# Created by MC2 : Version 2006.09.01.d on 2025/07/22, 15:52:49

###############################################################################
#        Software       : TSMC MEMORY COMPILER 2006.09.01.d
#        Technology     : 65 nm CMOS LOGIC Low Power LowK Cu 1P9M 1.2V
#                         Mixed-vt logic, High-vt SRAM
#        Memory Type    : TSMC 65nm Low Power Dual Port SRAM
#        Library Name   : tsdn65lplla1024x32m4s
#        Library Version: 200a
#        Generated Time : 2025/07/22, 15:52:48
###############################################################################
#
#STATEMENT OF USE
#
#This information contains confidential and proprietary information of TSMC.
#No part of this information may be reproduced, transmitted, transcribed,
#stored in a retrieval system, or translated into any human or computer
#language, in any form or by any means, electronic, mechanical, magnetic,
#optical, chemical, manual, or otherwise, without the prior written permission
#of TSMC. This information was prepared for informational purpose and is for
#use by TSMC's customers only. TSMC reserves the right to make changes in the
#information at any time and without notice.
#
###############################################################################
 
VERSION 5.5 ;
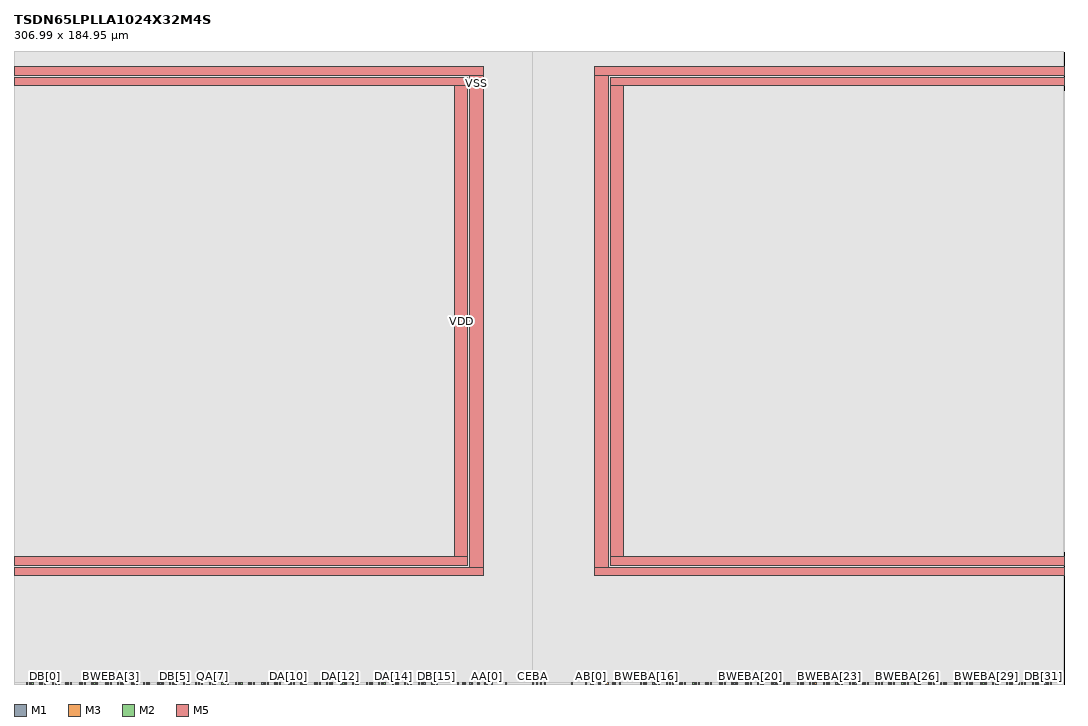
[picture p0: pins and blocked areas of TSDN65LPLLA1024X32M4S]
MACRO TSDN65LPLLA1024X32M4S
	CLASS BLOCK ;
	FOREIGN TSDN65LPLLA1024X32M4S 0.0 0.0 ;
	ORIGIN 0.0 0.0 ;
	SIZE 306.990 BY 184.950 ;
	SYMMETRY X Y R90 ;

	PIN AA[0]
		DIRECTION INPUT ;
		USE SIGNAL ;
		PORT
			LAYER M1 ;
			RECT 137.995 0.000 138.315 0.440 ;
			LAYER M3 ;
			RECT 137.995 0.000 138.315 0.440 ;
			LAYER M2 ;
			RECT 137.995 0.000 138.315 0.440 ;
		END
	END AA[0]

	PIN AA[1]
		DIRECTION INPUT ;
		USE SIGNAL ;
		PORT
			LAYER M1 ;
			RECT 139.555 0.000 139.875 0.440 ;
			LAYER M3 ;
			RECT 139.555 0.000 139.875 0.440 ;
			LAYER M2 ;
			RECT 139.555 0.000 139.875 0.440 ;
		END
	END AA[1]

	PIN AA[2]
		DIRECTION INPUT ;
		USE SIGNAL ;
		PORT
			LAYER M2 ;
			RECT 129.675 0.000 129.995 0.440 ;
			LAYER M3 ;
			RECT 129.675 0.000 129.995 0.440 ;
			LAYER M1 ;
			RECT 129.675 0.000 129.995 0.440 ;
		END
	END AA[2]

	PIN AA[3]
		DIRECTION INPUT ;
		USE SIGNAL ;
		PORT
			LAYER M3 ;
			RECT 131.235 0.000 131.555 0.440 ;
			LAYER M2 ;
			RECT 131.235 0.000 131.555 0.440 ;
			LAYER M1 ;
			RECT 131.235 0.000 131.555 0.440 ;
		END
	END AA[3]

	PIN AA[4]
		DIRECTION INPUT ;
		USE SIGNAL ;
		PORT
			LAYER M3 ;
			RECT 131.755 0.000 132.075 0.440 ;
			LAYER M2 ;
			RECT 131.755 0.000 132.075 0.440 ;
			LAYER M1 ;
			RECT 131.755 0.000 132.075 0.440 ;
		END
	END AA[4]

	PIN AA[5]
		DIRECTION INPUT ;
		USE SIGNAL ;
		PORT
			LAYER M3 ;
			RECT 135.915 0.000 136.235 0.440 ;
			LAYER M1 ;
			RECT 135.915 0.000 136.235 0.440 ;
			LAYER M2 ;
			RECT 135.915 0.000 136.235 0.440 ;
		END
	END AA[5]

	PIN AA[6]
		DIRECTION INPUT ;
		USE SIGNAL ;
		PORT
			LAYER M2 ;
			RECT 137.475 0.000 137.795 0.440 ;
			LAYER M1 ;
			RECT 137.475 0.000 137.795 0.440 ;
			LAYER M3 ;
			RECT 137.475 0.000 137.795 0.440 ;
		END
	END AA[6]

	PIN AA[7]
		DIRECTION INPUT ;
		USE SIGNAL ;
		PORT
			LAYER M2 ;
			RECT 135.395 0.000 135.715 0.440 ;
			LAYER M1 ;
			RECT 135.395 0.000 135.715 0.440 ;
			LAYER M3 ;
			RECT 135.395 0.000 135.715 0.440 ;
		END
	END AA[7]

	PIN AA[8]
		DIRECTION INPUT ;
		USE SIGNAL ;
		PORT
			LAYER M1 ;
			RECT 133.835 0.000 134.155 0.440 ;
			LAYER M2 ;
			RECT 133.835 0.000 134.155 0.440 ;
			LAYER M3 ;
			RECT 133.835 0.000 134.155 0.440 ;
		END
	END AA[8]

	PIN AA[9]
		DIRECTION INPUT ;
		USE SIGNAL ;
		PORT
			LAYER M2 ;
			RECT 133.315 0.000 133.635 0.440 ;
			LAYER M3 ;
			RECT 133.315 0.000 133.635 0.440 ;
			LAYER M1 ;
			RECT 133.315 0.000 133.635 0.440 ;
		END
	END AA[9]

	PIN AB[0]
		DIRECTION INPUT ;
		USE SIGNAL ;
		PORT
			LAYER M3 ;
			RECT 168.675 0.000 168.995 0.440 ;
			LAYER M1 ;
			RECT 168.675 0.000 168.995 0.440 ;
			LAYER M2 ;
			RECT 168.675 0.000 168.995 0.440 ;
		END
	END AB[0]

	PIN AB[1]
		DIRECTION INPUT ;
		USE SIGNAL ;
		PORT
			LAYER M1 ;
			RECT 167.115 0.000 167.435 0.440 ;
			LAYER M3 ;
			RECT 167.115 0.000 167.435 0.440 ;
			LAYER M2 ;
			RECT 167.115 0.000 167.435 0.440 ;
		END
	END AB[1]

	PIN AB[2]
		DIRECTION INPUT ;
		USE SIGNAL ;
		PORT
			LAYER M1 ;
			RECT 176.995 0.000 177.315 0.440 ;
			LAYER M2 ;
			RECT 176.995 0.000 177.315 0.440 ;
			LAYER M3 ;
			RECT 176.995 0.000 177.315 0.440 ;
		END
	END AB[2]

	PIN AB[3]
		DIRECTION INPUT ;
		USE SIGNAL ;
		PORT
			LAYER M1 ;
			RECT 175.435 0.000 175.755 0.440 ;
			LAYER M2 ;
			RECT 175.435 0.000 175.755 0.440 ;
			LAYER M3 ;
			RECT 175.435 0.000 175.755 0.440 ;
		END
	END AB[3]

	PIN AB[4]
		DIRECTION INPUT ;
		USE SIGNAL ;
		PORT
			LAYER M3 ;
			RECT 174.915 0.000 175.235 0.440 ;
			LAYER M2 ;
			RECT 174.915 0.000 175.235 0.440 ;
			LAYER M1 ;
			RECT 174.915 0.000 175.235 0.440 ;
		END
	END AB[4]

	PIN AB[5]
		DIRECTION INPUT ;
		USE SIGNAL ;
		PORT
			LAYER M3 ;
			RECT 170.755 0.000 171.075 0.440 ;
			LAYER M2 ;
			RECT 170.755 0.000 171.075 0.440 ;
			LAYER M1 ;
			RECT 170.755 0.000 171.075 0.440 ;
		END
	END AB[5]

	PIN AB[6]
		DIRECTION INPUT ;
		USE SIGNAL ;
		PORT
			LAYER M3 ;
			RECT 169.195 0.000 169.515 0.440 ;
			LAYER M2 ;
			RECT 169.195 0.000 169.515 0.440 ;
			LAYER M1 ;
			RECT 169.195 0.000 169.515 0.440 ;
		END
	END AB[6]

	PIN AB[7]
		DIRECTION INPUT ;
		USE SIGNAL ;
		PORT
			LAYER M3 ;
			RECT 171.275 0.000 171.595 0.440 ;
			LAYER M2 ;
			RECT 171.275 0.000 171.595 0.440 ;
			LAYER M1 ;
			RECT 171.275 0.000 171.595 0.440 ;
		END
	END AB[7]

	PIN AB[8]
		DIRECTION INPUT ;
		USE SIGNAL ;
		PORT
			LAYER M3 ;
			RECT 172.835 0.000 173.155 0.440 ;
			LAYER M2 ;
			RECT 172.835 0.000 173.155 0.440 ;
			LAYER M1 ;
			RECT 172.835 0.000 173.155 0.440 ;
		END
	END AB[8]

	PIN AB[9]
		DIRECTION INPUT ;
		USE SIGNAL ;
		PORT
			LAYER M2 ;
			RECT 173.355 0.000 173.675 0.440 ;
			LAYER M1 ;
			RECT 173.355 0.000 173.675 0.440 ;
			LAYER M3 ;
			RECT 173.355 0.000 173.675 0.440 ;
		END
	END AB[9]

	PIN BWEBA[0]
		DIRECTION INPUT ;
		USE SIGNAL ;
		PORT
			LAYER M3 ;
			RECT 5.245 0.000 5.565 0.440 ;
			LAYER M1 ;
			RECT 5.245 0.000 5.565 0.440 ;
			LAYER M2 ;
			RECT 5.245 0.000 5.565 0.440 ;
		END
	END BWEBA[0]

	PIN BWEBA[10]
		DIRECTION INPUT ;
		USE SIGNAL ;
		PORT
			LAYER M1 ;
			RECT 81.645 0.000 81.965 0.440 ;
			LAYER M3 ;
			RECT 81.645 0.000 81.965 0.440 ;
			LAYER M2 ;
			RECT 81.645 0.000 81.965 0.440 ;
		END
	END BWEBA[10]

	PIN BWEBA[11]
		DIRECTION INPUT ;
		USE SIGNAL ;
		PORT
			LAYER M2 ;
			RECT 89.285 0.000 89.605 0.440 ;
			LAYER M3 ;
			RECT 89.285 0.000 89.605 0.440 ;
			LAYER M1 ;
			RECT 89.285 0.000 89.605 0.440 ;
		END
	END BWEBA[11]

	PIN BWEBA[12]
		DIRECTION INPUT ;
		USE SIGNAL ;
		PORT
			LAYER M2 ;
			RECT 96.925 0.000 97.245 0.440 ;
			LAYER M1 ;
			RECT 96.925 0.000 97.245 0.440 ;
			LAYER M3 ;
			RECT 96.925 0.000 97.245 0.440 ;
		END
	END BWEBA[12]

	PIN BWEBA[13]
		DIRECTION INPUT ;
		USE SIGNAL ;
		PORT
			LAYER M1 ;
			RECT 104.565 0.000 104.885 0.440 ;
			LAYER M2 ;
			RECT 104.565 0.000 104.885 0.440 ;
			LAYER M3 ;
			RECT 104.565 0.000 104.885 0.440 ;
		END
	END BWEBA[13]

	PIN BWEBA[14]
		DIRECTION INPUT ;
		USE SIGNAL ;
		PORT
			LAYER M1 ;
			RECT 112.205 0.000 112.525 0.440 ;
			LAYER M2 ;
			RECT 112.205 0.000 112.525 0.440 ;
			LAYER M3 ;
			RECT 112.205 0.000 112.525 0.440 ;
		END
	END BWEBA[14]

	PIN BWEBA[15]
		DIRECTION INPUT ;
		USE SIGNAL ;
		PORT
			LAYER M3 ;
			RECT 119.845 0.000 120.165 0.440 ;
			LAYER M2 ;
			RECT 119.845 0.000 120.165 0.440 ;
			LAYER M1 ;
			RECT 119.845 0.000 120.165 0.440 ;
		END
	END BWEBA[15]

	PIN BWEBA[16]
		DIRECTION INPUT ;
		USE SIGNAL ;
		PORT
			LAYER M2 ;
			RECT 184.745 0.000 185.065 0.440 ;
			LAYER M3 ;
			RECT 184.745 0.000 185.065 0.440 ;
			LAYER M1 ;
			RECT 184.745 0.000 185.065 0.440 ;
		END
	END BWEBA[16]

	PIN BWEBA[17]
		DIRECTION INPUT ;
		USE SIGNAL ;
		PORT
			LAYER M3 ;
			RECT 192.385 0.000 192.705 0.440 ;
			LAYER M2 ;
			RECT 192.385 0.000 192.705 0.440 ;
			LAYER M1 ;
			RECT 192.385 0.000 192.705 0.440 ;
		END
	END BWEBA[17]

	PIN BWEBA[18]
		DIRECTION INPUT ;
		USE SIGNAL ;
		PORT
			LAYER M2 ;
			RECT 200.025 0.000 200.345 0.440 ;
			LAYER M1 ;
			RECT 200.025 0.000 200.345 0.440 ;
			LAYER M3 ;
			RECT 200.025 0.000 200.345 0.440 ;
		END
	END BWEBA[18]

	PIN BWEBA[19]
		DIRECTION INPUT ;
		USE SIGNAL ;
		PORT
			LAYER M1 ;
			RECT 207.665 0.000 207.985 0.440 ;
			LAYER M3 ;
			RECT 207.665 0.000 207.985 0.440 ;
			LAYER M2 ;
			RECT 207.665 0.000 207.985 0.440 ;
		END
	END BWEBA[19]

	PIN BWEBA[1]
		DIRECTION INPUT ;
		USE SIGNAL ;
		PORT
			LAYER M3 ;
			RECT 12.885 0.000 13.205 0.440 ;
			LAYER M2 ;
			RECT 12.885 0.000 13.205 0.440 ;
			LAYER M1 ;
			RECT 12.885 0.000 13.205 0.440 ;
		END
	END BWEBA[1]

	PIN BWEBA[20]
		DIRECTION INPUT ;
		USE SIGNAL ;
		PORT
			LAYER M2 ;
			RECT 215.305 0.000 215.625 0.440 ;
			LAYER M1 ;
			RECT 215.305 0.000 215.625 0.440 ;
			LAYER M3 ;
			RECT 215.305 0.000 215.625 0.440 ;
		END
	END BWEBA[20]

	PIN BWEBA[21]
		DIRECTION INPUT ;
		USE SIGNAL ;
		PORT
			LAYER M2 ;
			RECT 222.945 0.000 223.265 0.440 ;
			LAYER M3 ;
			RECT 222.945 0.000 223.265 0.440 ;
			LAYER M1 ;
			RECT 222.945 0.000 223.265 0.440 ;
		END
	END BWEBA[21]

	PIN BWEBA[22]
		DIRECTION INPUT ;
		USE SIGNAL ;
		PORT
			LAYER M2 ;
			RECT 230.585 0.000 230.905 0.440 ;
			LAYER M3 ;
			RECT 230.585 0.000 230.905 0.440 ;
			LAYER M1 ;
			RECT 230.585 0.000 230.905 0.440 ;
		END
	END BWEBA[22]

	PIN BWEBA[23]
		DIRECTION INPUT ;
		USE SIGNAL ;
		PORT
			LAYER M3 ;
			RECT 238.225 0.000 238.545 0.440 ;
			LAYER M1 ;
			RECT 238.225 0.000 238.545 0.440 ;
			LAYER M2 ;
			RECT 238.225 0.000 238.545 0.440 ;
		END
	END BWEBA[23]

	PIN BWEBA[24]
		DIRECTION INPUT ;
		USE SIGNAL ;
		PORT
			LAYER M3 ;
			RECT 245.865 0.000 246.185 0.440 ;
			LAYER M2 ;
			RECT 245.865 0.000 246.185 0.440 ;
			LAYER M1 ;
			RECT 245.865 0.000 246.185 0.440 ;
		END
	END BWEBA[24]

	PIN BWEBA[25]
		DIRECTION INPUT ;
		USE SIGNAL ;
		PORT
			LAYER M1 ;
			RECT 253.505 0.000 253.825 0.440 ;
			LAYER M3 ;
			RECT 253.505 0.000 253.825 0.440 ;
			LAYER M2 ;
			RECT 253.505 0.000 253.825 0.440 ;
		END
	END BWEBA[25]

	PIN BWEBA[26]
		DIRECTION INPUT ;
		USE SIGNAL ;
		PORT
			LAYER M1 ;
			RECT 261.145 0.000 261.465 0.440 ;
			LAYER M3 ;
			RECT 261.145 0.000 261.465 0.440 ;
			LAYER M2 ;
			RECT 261.145 0.000 261.465 0.440 ;
		END
	END BWEBA[26]

	PIN BWEBA[27]
		DIRECTION INPUT ;
		USE SIGNAL ;
		PORT
			LAYER M1 ;
			RECT 268.785 0.000 269.105 0.440 ;
			LAYER M3 ;
			RECT 268.785 0.000 269.105 0.440 ;
			LAYER M2 ;
			RECT 268.785 0.000 269.105 0.440 ;
		END
	END BWEBA[27]

	PIN BWEBA[28]
		DIRECTION INPUT ;
		USE SIGNAL ;
		PORT
			LAYER M3 ;
			RECT 276.425 0.000 276.745 0.440 ;
			LAYER M2 ;
			RECT 276.425 0.000 276.745 0.440 ;
			LAYER M1 ;
			RECT 276.425 0.000 276.745 0.440 ;
		END
	END BWEBA[28]

	PIN BWEBA[29]
		DIRECTION INPUT ;
		USE SIGNAL ;
		PORT
			LAYER M1 ;
			RECT 284.065 0.000 284.385 0.440 ;
			LAYER M3 ;
			RECT 284.065 0.000 284.385 0.440 ;
			LAYER M2 ;
			RECT 284.065 0.000 284.385 0.440 ;
		END
	END BWEBA[29]

	PIN BWEBA[2]
		DIRECTION INPUT ;
		USE SIGNAL ;
		PORT
			LAYER M2 ;
			RECT 20.525 0.000 20.845 0.440 ;
			LAYER M3 ;
			RECT 20.525 0.000 20.845 0.440 ;
			LAYER M1 ;
			RECT 20.525 0.000 20.845 0.440 ;
		END
	END BWEBA[2]

	PIN BWEBA[30]
		DIRECTION INPUT ;
		USE SIGNAL ;
		PORT
			LAYER M1 ;
			RECT 291.705 0.000 292.025 0.440 ;
			LAYER M2 ;
			RECT 291.705 0.000 292.025 0.440 ;
			LAYER M3 ;
			RECT 291.705 0.000 292.025 0.440 ;
		END
	END BWEBA[30]

	PIN BWEBA[31]
		DIRECTION INPUT ;
		USE SIGNAL ;
		PORT
			LAYER M3 ;
			RECT 299.345 0.000 299.665 0.440 ;
			LAYER M1 ;
			RECT 299.345 0.000 299.665 0.440 ;
			LAYER M2 ;
			RECT 299.345 0.000 299.665 0.440 ;
		END
	END BWEBA[31]

	PIN BWEBA[3]
		DIRECTION INPUT ;
		USE SIGNAL ;
		PORT
			LAYER M3 ;
			RECT 28.165 0.000 28.485 0.440 ;
			LAYER M1 ;
			RECT 28.165 0.000 28.485 0.440 ;
			LAYER M2 ;
			RECT 28.165 0.000 28.485 0.440 ;
		END
	END BWEBA[3]

	PIN BWEBA[4]
		DIRECTION INPUT ;
		USE SIGNAL ;
		PORT
			LAYER M2 ;
			RECT 35.805 0.000 36.125 0.440 ;
			LAYER M1 ;
			RECT 35.805 0.000 36.125 0.440 ;
			LAYER M3 ;
			RECT 35.805 0.000 36.125 0.440 ;
		END
	END BWEBA[4]

	PIN BWEBA[5]
		DIRECTION INPUT ;
		USE SIGNAL ;
		PORT
			LAYER M2 ;
			RECT 43.445 0.000 43.765 0.440 ;
			LAYER M3 ;
			RECT 43.445 0.000 43.765 0.440 ;
			LAYER M1 ;
			RECT 43.445 0.000 43.765 0.440 ;
		END
	END BWEBA[5]

	PIN BWEBA[6]
		DIRECTION INPUT ;
		USE SIGNAL ;
		PORT
			LAYER M2 ;
			RECT 51.085 0.000 51.405 0.440 ;
			LAYER M3 ;
			RECT 51.085 0.000 51.405 0.440 ;
			LAYER M1 ;
			RECT 51.085 0.000 51.405 0.440 ;
		END
	END BWEBA[6]

	PIN BWEBA[7]
		DIRECTION INPUT ;
		USE SIGNAL ;
		PORT
			LAYER M3 ;
			RECT 58.725 0.000 59.045 0.440 ;
			LAYER M1 ;
			RECT 58.725 0.000 59.045 0.440 ;
			LAYER M2 ;
			RECT 58.725 0.000 59.045 0.440 ;
		END
	END BWEBA[7]

	PIN BWEBA[8]
		DIRECTION INPUT ;
		USE SIGNAL ;
		PORT
			LAYER M3 ;
			RECT 66.365 0.000 66.685 0.440 ;
			LAYER M1 ;
			RECT 66.365 0.000 66.685 0.440 ;
			LAYER M2 ;
			RECT 66.365 0.000 66.685 0.440 ;
		END
	END BWEBA[8]

	PIN BWEBA[9]
		DIRECTION INPUT ;
		USE SIGNAL ;
		PORT
			LAYER M3 ;
			RECT 74.005 0.000 74.325 0.440 ;
			LAYER M2 ;
			RECT 74.005 0.000 74.325 0.440 ;
			LAYER M1 ;
			RECT 74.005 0.000 74.325 0.440 ;
		END
	END BWEBA[9]

	PIN BWEBB[0]
		DIRECTION INPUT ;
		USE SIGNAL ;
		PORT
			LAYER M2 ;
			RECT 7.325 0.000 7.645 0.440 ;
			LAYER M3 ;
			RECT 7.325 0.000 7.645 0.440 ;
			LAYER M1 ;
			RECT 7.325 0.000 7.645 0.440 ;
		END
	END BWEBB[0]

	PIN BWEBB[10]
		DIRECTION INPUT ;
		USE SIGNAL ;
		PORT
			LAYER M2 ;
			RECT 83.725 0.000 84.045 0.440 ;
			LAYER M1 ;
			RECT 83.725 0.000 84.045 0.440 ;
			LAYER M3 ;
			RECT 83.725 0.000 84.045 0.440 ;
		END
	END BWEBB[10]

	PIN BWEBB[11]
		DIRECTION INPUT ;
		USE SIGNAL ;
		PORT
			LAYER M2 ;
			RECT 91.365 0.000 91.685 0.440 ;
			LAYER M3 ;
			RECT 91.365 0.000 91.685 0.440 ;
			LAYER M1 ;
			RECT 91.365 0.000 91.685 0.440 ;
		END
	END BWEBB[11]

	PIN BWEBB[12]
		DIRECTION INPUT ;
		USE SIGNAL ;
		PORT
			LAYER M1 ;
			RECT 99.005 0.000 99.325 0.440 ;
			LAYER M2 ;
			RECT 99.005 0.000 99.325 0.440 ;
			LAYER M3 ;
			RECT 99.005 0.000 99.325 0.440 ;
		END
	END BWEBB[12]

	PIN BWEBB[13]
		DIRECTION INPUT ;
		USE SIGNAL ;
		PORT
			LAYER M3 ;
			RECT 106.645 0.000 106.965 0.440 ;
			LAYER M1 ;
			RECT 106.645 0.000 106.965 0.440 ;
			LAYER M2 ;
			RECT 106.645 0.000 106.965 0.440 ;
		END
	END BWEBB[13]

	PIN BWEBB[14]
		DIRECTION INPUT ;
		USE SIGNAL ;
		PORT
			LAYER M1 ;
			RECT 114.285 0.000 114.605 0.440 ;
			LAYER M3 ;
			RECT 114.285 0.000 114.605 0.440 ;
			LAYER M2 ;
			RECT 114.285 0.000 114.605 0.440 ;
		END
	END BWEBB[14]

	PIN BWEBB[15]
		DIRECTION INPUT ;
		USE SIGNAL ;
		PORT
			LAYER M2 ;
			RECT 121.925 0.000 122.245 0.440 ;
			LAYER M3 ;
			RECT 121.925 0.000 122.245 0.440 ;
			LAYER M1 ;
			RECT 121.925 0.000 122.245 0.440 ;
		END
	END BWEBB[15]

	PIN BWEBB[16]
		DIRECTION INPUT ;
		USE SIGNAL ;
		PORT
			LAYER M2 ;
			RECT 186.825 0.000 187.145 0.440 ;
			LAYER M3 ;
			RECT 186.825 0.000 187.145 0.440 ;
			LAYER M1 ;
			RECT 186.825 0.000 187.145 0.440 ;
		END
	END BWEBB[16]

	PIN BWEBB[17]
		DIRECTION INPUT ;
		USE SIGNAL ;
		PORT
			LAYER M2 ;
			RECT 194.465 0.000 194.785 0.440 ;
			LAYER M3 ;
			RECT 194.465 0.000 194.785 0.440 ;
			LAYER M1 ;
			RECT 194.465 0.000 194.785 0.440 ;
		END
	END BWEBB[17]

	PIN BWEBB[18]
		DIRECTION INPUT ;
		USE SIGNAL ;
		PORT
			LAYER M2 ;
			RECT 202.105 0.000 202.425 0.440 ;
			LAYER M3 ;
			RECT 202.105 0.000 202.425 0.440 ;
			LAYER M1 ;
			RECT 202.105 0.000 202.425 0.440 ;
		END
	END BWEBB[18]

	PIN BWEBB[19]
		DIRECTION INPUT ;
		USE SIGNAL ;
		PORT
			LAYER M2 ;
			RECT 209.745 0.000 210.065 0.440 ;
			LAYER M1 ;
			RECT 209.745 0.000 210.065 0.440 ;
			LAYER M3 ;
			RECT 209.745 0.000 210.065 0.440 ;
		END
	END BWEBB[19]

	PIN BWEBB[1]
		DIRECTION INPUT ;
		USE SIGNAL ;
		PORT
			LAYER M1 ;
			RECT 14.965 0.000 15.285 0.440 ;
			LAYER M2 ;
			RECT 14.965 0.000 15.285 0.440 ;
			LAYER M3 ;
			RECT 14.965 0.000 15.285 0.440 ;
		END
	END BWEBB[1]

	PIN BWEBB[20]
		DIRECTION INPUT ;
		USE SIGNAL ;
		PORT
			LAYER M1 ;
			RECT 217.385 0.000 217.705 0.440 ;
			LAYER M2 ;
			RECT 217.385 0.000 217.705 0.440 ;
			LAYER M3 ;
			RECT 217.385 0.000 217.705 0.440 ;
		END
	END BWEBB[20]

	PIN BWEBB[21]
		DIRECTION INPUT ;
		USE SIGNAL ;
		PORT
			LAYER M1 ;
			RECT 225.025 0.000 225.345 0.440 ;
			LAYER M2 ;
			RECT 225.025 0.000 225.345 0.440 ;
			LAYER M3 ;
			RECT 225.025 0.000 225.345 0.440 ;
		END
	END BWEBB[21]

	PIN BWEBB[22]
		DIRECTION INPUT ;
		USE SIGNAL ;
		PORT
			LAYER M1 ;
			RECT 232.665 0.000 232.985 0.440 ;
			LAYER M3 ;
			RECT 232.665 0.000 232.985 0.440 ;
			LAYER M2 ;
			RECT 232.665 0.000 232.985 0.440 ;
		END
	END BWEBB[22]

	PIN BWEBB[23]
		DIRECTION INPUT ;
		USE SIGNAL ;
		PORT
			LAYER M3 ;
			RECT 240.305 0.000 240.625 0.440 ;
			LAYER M2 ;
			RECT 240.305 0.000 240.625 0.440 ;
			LAYER M1 ;
			RECT 240.305 0.000 240.625 0.440 ;
		END
	END BWEBB[23]

	PIN BWEBB[24]
		DIRECTION INPUT ;
		USE SIGNAL ;
		PORT
			LAYER M2 ;
			RECT 247.945 0.000 248.265 0.440 ;
			LAYER M3 ;
			RECT 247.945 0.000 248.265 0.440 ;
			LAYER M1 ;
			RECT 247.945 0.000 248.265 0.440 ;
		END
	END BWEBB[24]

	PIN BWEBB[25]
		DIRECTION INPUT ;
		USE SIGNAL ;
		PORT
			LAYER M1 ;
			RECT 255.585 0.000 255.905 0.440 ;
			LAYER M2 ;
			RECT 255.585 0.000 255.905 0.440 ;
			LAYER M3 ;
			RECT 255.585 0.000 255.905 0.440 ;
		END
	END BWEBB[25]

	PIN BWEBB[26]
		DIRECTION INPUT ;
		USE SIGNAL ;
		PORT
			LAYER M1 ;
			RECT 263.225 0.000 263.545 0.440 ;
			LAYER M3 ;
			RECT 263.225 0.000 263.545 0.440 ;
			LAYER M2 ;
			RECT 263.225 0.000 263.545 0.440 ;
		END
	END BWEBB[26]

	PIN BWEBB[27]
		DIRECTION INPUT ;
		USE SIGNAL ;
		PORT
			LAYER M3 ;
			RECT 270.865 0.000 271.185 0.440 ;
			LAYER M1 ;
			RECT 270.865 0.000 271.185 0.440 ;
			LAYER M2 ;
			RECT 270.865 0.000 271.185 0.440 ;
		END
	END BWEBB[27]

	PIN BWEBB[28]
		DIRECTION INPUT ;
		USE SIGNAL ;
		PORT
			LAYER M1 ;
			RECT 278.505 0.000 278.825 0.440 ;
			LAYER M2 ;
			RECT 278.505 0.000 278.825 0.440 ;
			LAYER M3 ;
			RECT 278.505 0.000 278.825 0.440 ;
		END
	END BWEBB[28]

	PIN BWEBB[29]
		DIRECTION INPUT ;
		USE SIGNAL ;
		PORT
			LAYER M3 ;
			RECT 286.145 0.000 286.465 0.440 ;
			LAYER M1 ;
			RECT 286.145 0.000 286.465 0.440 ;
			LAYER M2 ;
			RECT 286.145 0.000 286.465 0.440 ;
		END
	END BWEBB[29]

	PIN BWEBB[2]
		DIRECTION INPUT ;
		USE SIGNAL ;
		PORT
			LAYER M2 ;
			RECT 22.605 0.000 22.925 0.440 ;
			LAYER M3 ;
			RECT 22.605 0.000 22.925 0.440 ;
			LAYER M1 ;
			RECT 22.605 0.000 22.925 0.440 ;
		END
	END BWEBB[2]

	PIN BWEBB[30]
		DIRECTION INPUT ;
		USE SIGNAL ;
		PORT
			LAYER M1 ;
			RECT 293.785 0.000 294.105 0.440 ;
			LAYER M3 ;
			RECT 293.785 0.000 294.105 0.440 ;
			LAYER M2 ;
			RECT 293.785 0.000 294.105 0.440 ;
		END
	END BWEBB[30]

	PIN BWEBB[31]
		DIRECTION INPUT ;
		USE SIGNAL ;
		PORT
			LAYER M2 ;
			RECT 301.425 0.000 301.745 0.440 ;
			LAYER M3 ;
			RECT 301.425 0.000 301.745 0.440 ;
			LAYER M1 ;
			RECT 301.425 0.000 301.745 0.440 ;
		END
	END BWEBB[31]

	PIN BWEBB[3]
		DIRECTION INPUT ;
		USE SIGNAL ;
		PORT
			LAYER M1 ;
			RECT 30.245 0.000 30.565 0.440 ;
			LAYER M2 ;
			RECT 30.245 0.000 30.565 0.440 ;
			LAYER M3 ;
			RECT 30.245 0.000 30.565 0.440 ;
		END
	END BWEBB[3]

	PIN BWEBB[4]
		DIRECTION INPUT ;
		USE SIGNAL ;
		PORT
			LAYER M2 ;
			RECT 37.885 0.000 38.205 0.440 ;
			LAYER M3 ;
			RECT 37.885 0.000 38.205 0.440 ;
			LAYER M1 ;
			RECT 37.885 0.000 38.205 0.440 ;
		END
	END BWEBB[4]

	PIN BWEBB[5]
		DIRECTION INPUT ;
		USE SIGNAL ;
		PORT
			LAYER M3 ;
			RECT 45.525 0.000 45.845 0.440 ;
			LAYER M1 ;
			RECT 45.525 0.000 45.845 0.440 ;
			LAYER M2 ;
			RECT 45.525 0.000 45.845 0.440 ;
		END
	END BWEBB[5]

	PIN BWEBB[6]
		DIRECTION INPUT ;
		USE SIGNAL ;
		PORT
			LAYER M1 ;
			RECT 53.165 0.000 53.485 0.440 ;
			LAYER M3 ;
			RECT 53.165 0.000 53.485 0.440 ;
			LAYER M2 ;
			RECT 53.165 0.000 53.485 0.440 ;
		END
	END BWEBB[6]

	PIN BWEBB[7]
		DIRECTION INPUT ;
		USE SIGNAL ;
		PORT
			LAYER M1 ;
			RECT 60.805 0.000 61.125 0.440 ;
			LAYER M3 ;
			RECT 60.805 0.000 61.125 0.440 ;
			LAYER M2 ;
			RECT 60.805 0.000 61.125 0.440 ;
		END
	END BWEBB[7]

	PIN BWEBB[8]
		DIRECTION INPUT ;
		USE SIGNAL ;
		PORT
			LAYER M2 ;
			RECT 68.445 0.000 68.765 0.440 ;
			LAYER M3 ;
			RECT 68.445 0.000 68.765 0.440 ;
			LAYER M1 ;
			RECT 68.445 0.000 68.765 0.440 ;
		END
	END BWEBB[8]

	PIN BWEBB[9]
		DIRECTION INPUT ;
		USE SIGNAL ;
		PORT
			LAYER M2 ;
			RECT 76.085 0.000 76.405 0.440 ;
			LAYER M1 ;
			RECT 76.085 0.000 76.405 0.440 ;
			LAYER M3 ;
			RECT 76.085 0.000 76.405 0.440 ;
		END
	END BWEBB[9]

	PIN CEBA
		DIRECTION INPUT ;
		USE SIGNAL ;
		PORT
			LAYER M1 ;
			RECT 151.655 0.000 151.975 0.445 ;
			LAYER M2 ;
			RECT 151.655 0.000 151.975 0.445 ;
			LAYER M3 ;
			RECT 151.655 0.000 151.975 0.445 ;
		END
	END CEBA

	PIN CEBB
		DIRECTION INPUT ;
		USE SIGNAL ;
		PORT
			LAYER M1 ;
			RECT 155.015 0.000 155.335 0.445 ;
			LAYER M2 ;
			RECT 155.015 0.000 155.335 0.445 ;
			LAYER M3 ;
			RECT 155.015 0.000 155.335 0.445 ;
		END
	END CEBB

	PIN CLKA
		DIRECTION INPUT ;
		USE SIGNAL ;
		PORT
			LAYER M1 ;
			RECT 152.775 0.000 153.095 0.445 ;
			LAYER M2 ;
			RECT 152.775 0.000 153.095 0.445 ;
			LAYER M3 ;
			RECT 152.775 0.000 153.095 0.445 ;
		END
	END CLKA

	PIN CLKB
		DIRECTION INPUT ;
		USE SIGNAL ;
		PORT
			LAYER M3 ;
			RECT 153.895 0.000 154.215 0.445 ;
			LAYER M1 ;
			RECT 153.895 0.000 154.215 0.445 ;
			LAYER M2 ;
			RECT 153.895 0.000 154.215 0.445 ;
		END
	END CLKB

	PIN DA[0]
		DIRECTION INPUT ;
		USE SIGNAL ;
		PORT
			LAYER M3 ;
			RECT 3.725 0.000 4.045 0.440 ;
			LAYER M1 ;
			RECT 3.725 0.000 4.045 0.440 ;
			LAYER M2 ;
			RECT 3.725 0.000 4.045 0.440 ;
		END
	END DA[0]

	PIN DA[10]
		DIRECTION INPUT ;
		USE SIGNAL ;
		PORT
			LAYER M3 ;
			RECT 80.125 0.000 80.445 0.440 ;
			LAYER M1 ;
			RECT 80.125 0.000 80.445 0.440 ;
			LAYER M2 ;
			RECT 80.125 0.000 80.445 0.440 ;
		END
	END DA[10]

	PIN DA[11]
		DIRECTION INPUT ;
		USE SIGNAL ;
		PORT
			LAYER M3 ;
			RECT 87.765 0.000 88.085 0.440 ;
			LAYER M1 ;
			RECT 87.765 0.000 88.085 0.440 ;
			LAYER M2 ;
			RECT 87.765 0.000 88.085 0.440 ;
		END
	END DA[11]

	PIN DA[12]
		DIRECTION INPUT ;
		USE SIGNAL ;
		PORT
			LAYER M3 ;
			RECT 95.405 0.000 95.725 0.440 ;
			LAYER M1 ;
			RECT 95.405 0.000 95.725 0.440 ;
			LAYER M2 ;
			RECT 95.405 0.000 95.725 0.440 ;
		END
	END DA[12]

	PIN DA[13]
		DIRECTION INPUT ;
		USE SIGNAL ;
		PORT
			LAYER M3 ;
			RECT 103.045 0.000 103.365 0.440 ;
			LAYER M1 ;
			RECT 103.045 0.000 103.365 0.440 ;
			LAYER M2 ;
			RECT 103.045 0.000 103.365 0.440 ;
		END
	END DA[13]

	PIN DA[14]
		DIRECTION INPUT ;
		USE SIGNAL ;
		PORT
			LAYER M2 ;
			RECT 110.685 0.000 111.005 0.440 ;
			LAYER M3 ;
			RECT 110.685 0.000 111.005 0.440 ;
			LAYER M1 ;
			RECT 110.685 0.000 111.005 0.440 ;
		END
	END DA[14]

	PIN DA[15]
		DIRECTION INPUT ;
		USE SIGNAL ;
		PORT
			LAYER M2 ;
			RECT 118.325 0.000 118.645 0.440 ;
			LAYER M3 ;
			RECT 118.325 0.000 118.645 0.440 ;
			LAYER M1 ;
			RECT 118.325 0.000 118.645 0.440 ;
		END
	END DA[15]

	PIN DA[16]
		DIRECTION INPUT ;
		USE SIGNAL ;
		PORT
			LAYER M3 ;
			RECT 183.225 0.000 183.545 0.440 ;
			LAYER M1 ;
			RECT 183.225 0.000 183.545 0.440 ;
			LAYER M2 ;
			RECT 183.225 0.000 183.545 0.440 ;
		END
	END DA[16]

	PIN DA[17]
		DIRECTION INPUT ;
		USE SIGNAL ;
		PORT
			LAYER M3 ;
			RECT 190.865 0.000 191.185 0.440 ;
			LAYER M1 ;
			RECT 190.865 0.000 191.185 0.440 ;
			LAYER M2 ;
			RECT 190.865 0.000 191.185 0.440 ;
		END
	END DA[17]

	PIN DA[18]
		DIRECTION INPUT ;
		USE SIGNAL ;
		PORT
			LAYER M3 ;
			RECT 198.505 0.000 198.825 0.440 ;
			LAYER M1 ;
			RECT 198.505 0.000 198.825 0.440 ;
			LAYER M2 ;
			RECT 198.505 0.000 198.825 0.440 ;
		END
	END DA[18]

	PIN DA[19]
		DIRECTION INPUT ;
		USE SIGNAL ;
		PORT
			LAYER M1 ;
			RECT 206.145 0.000 206.465 0.440 ;
			LAYER M3 ;
			RECT 206.145 0.000 206.465 0.440 ;
			LAYER M2 ;
			RECT 206.145 0.000 206.465 0.440 ;
		END
	END DA[19]

	PIN DA[1]
		DIRECTION INPUT ;
		USE SIGNAL ;
		PORT
			LAYER M3 ;
			RECT 11.365 0.000 11.685 0.440 ;
			LAYER M1 ;
			RECT 11.365 0.000 11.685 0.440 ;
			LAYER M2 ;
			RECT 11.365 0.000 11.685 0.440 ;
		END
	END DA[1]

	PIN DA[20]
		DIRECTION INPUT ;
		USE SIGNAL ;
		PORT
			LAYER M1 ;
			RECT 213.785 0.000 214.105 0.440 ;
			LAYER M2 ;
			RECT 213.785 0.000 214.105 0.440 ;
			LAYER M3 ;
			RECT 213.785 0.000 214.105 0.440 ;
		END
	END DA[20]

	PIN DA[21]
		DIRECTION INPUT ;
		USE SIGNAL ;
		PORT
			LAYER M3 ;
			RECT 221.425 0.000 221.745 0.440 ;
			LAYER M2 ;
			RECT 221.425 0.000 221.745 0.440 ;
			LAYER M1 ;
			RECT 221.425 0.000 221.745 0.440 ;
		END
	END DA[21]

	PIN DA[22]
		DIRECTION INPUT ;
		USE SIGNAL ;
		PORT
			LAYER M1 ;
			RECT 229.065 0.000 229.385 0.440 ;
			LAYER M2 ;
			RECT 229.065 0.000 229.385 0.440 ;
			LAYER M3 ;
			RECT 229.065 0.000 229.385 0.440 ;
		END
	END DA[22]

	PIN DA[23]
		DIRECTION INPUT ;
		USE SIGNAL ;
		PORT
			LAYER M3 ;
			RECT 236.705 0.000 237.025 0.440 ;
			LAYER M1 ;
			RECT 236.705 0.000 237.025 0.440 ;
			LAYER M2 ;
			RECT 236.705 0.000 237.025 0.440 ;
		END
	END DA[23]

	PIN DA[24]
		DIRECTION INPUT ;
		USE SIGNAL ;
		PORT
			LAYER M3 ;
			RECT 244.345 0.000 244.665 0.440 ;
			LAYER M1 ;
			RECT 244.345 0.000 244.665 0.440 ;
			LAYER M2 ;
			RECT 244.345 0.000 244.665 0.440 ;
		END
	END DA[24]

	PIN DA[25]
		DIRECTION INPUT ;
		USE SIGNAL ;
		PORT
			LAYER M3 ;
			RECT 251.985 0.000 252.305 0.440 ;
			LAYER M1 ;
			RECT 251.985 0.000 252.305 0.440 ;
			LAYER M2 ;
			RECT 251.985 0.000 252.305 0.440 ;
		END
	END DA[25]

	PIN DA[26]
		DIRECTION INPUT ;
		USE SIGNAL ;
		PORT
			LAYER M3 ;
			RECT 259.625 0.000 259.945 0.440 ;
			LAYER M1 ;
			RECT 259.625 0.000 259.945 0.440 ;
			LAYER M2 ;
			RECT 259.625 0.000 259.945 0.440 ;
		END
	END DA[26]

	PIN DA[27]
		DIRECTION INPUT ;
		USE SIGNAL ;
		PORT
			LAYER M3 ;
			RECT 267.265 0.000 267.585 0.440 ;
			LAYER M1 ;
			RECT 267.265 0.000 267.585 0.440 ;
			LAYER M2 ;
			RECT 267.265 0.000 267.585 0.440 ;
		END
	END DA[27]

	PIN DA[28]
		DIRECTION INPUT ;
		USE SIGNAL ;
		PORT
			LAYER M3 ;
			RECT 274.905 0.000 275.225 0.440 ;
			LAYER M1 ;
			RECT 274.905 0.000 275.225 0.440 ;
			LAYER M2 ;
			RECT 274.905 0.000 275.225 0.440 ;
		END
	END DA[28]

	PIN DA[29]
		DIRECTION INPUT ;
		USE SIGNAL ;
		PORT
			LAYER M3 ;
			RECT 282.545 0.000 282.865 0.440 ;
			LAYER M1 ;
			RECT 282.545 0.000 282.865 0.440 ;
			LAYER M2 ;
			RECT 282.545 0.000 282.865 0.440 ;
		END
	END DA[29]

	PIN DA[2]
		DIRECTION INPUT ;
		USE SIGNAL ;
		PORT
			LAYER M3 ;
			RECT 19.005 0.000 19.325 0.440 ;
			LAYER M1 ;
			RECT 19.005 0.000 19.325 0.440 ;
			LAYER M2 ;
			RECT 19.005 0.000 19.325 0.440 ;
		END
	END DA[2]

	PIN DA[30]
		DIRECTION INPUT ;
		USE SIGNAL ;
		PORT
			LAYER M3 ;
			RECT 290.185 0.000 290.505 0.440 ;
			LAYER M2 ;
			RECT 290.185 0.000 290.505 0.440 ;
			LAYER M1 ;
			RECT 290.185 0.000 290.505 0.440 ;
		END
	END DA[30]

	PIN DA[31]
		DIRECTION INPUT ;
		USE SIGNAL ;
		PORT
			LAYER M1 ;
			RECT 297.825 0.000 298.145 0.440 ;
			LAYER M3 ;
			RECT 297.825 0.000 298.145 0.440 ;
			LAYER M2 ;
			RECT 297.825 0.000 298.145 0.440 ;
		END
	END DA[31]

	PIN DA[3]
		DIRECTION INPUT ;
		USE SIGNAL ;
		PORT
			LAYER M1 ;
			RECT 26.645 0.000 26.965 0.440 ;
			LAYER M3 ;
			RECT 26.645 0.000 26.965 0.440 ;
			LAYER M2 ;
			RECT 26.645 0.000 26.965 0.440 ;
		END
	END DA[3]

	PIN DA[4]
		DIRECTION INPUT ;
		USE SIGNAL ;
		PORT
			LAYER M1 ;
			RECT 34.285 0.000 34.605 0.440 ;
			LAYER M2 ;
			RECT 34.285 0.000 34.605 0.440 ;
			LAYER M3 ;
			RECT 34.285 0.000 34.605 0.440 ;
		END
	END DA[4]

	PIN DA[5]
		DIRECTION INPUT ;
		USE SIGNAL ;
		PORT
			LAYER M3 ;
			RECT 41.925 0.000 42.245 0.440 ;
			LAYER M2 ;
			RECT 41.925 0.000 42.245 0.440 ;
			LAYER M1 ;
			RECT 41.925 0.000 42.245 0.440 ;
		END
	END DA[5]

	PIN DA[6]
		DIRECTION INPUT ;
		USE SIGNAL ;
		PORT
			LAYER M1 ;
			RECT 49.565 0.000 49.885 0.440 ;
			LAYER M2 ;
			RECT 49.565 0.000 49.885 0.440 ;
			LAYER M3 ;
			RECT 49.565 0.000 49.885 0.440 ;
		END
	END DA[6]

	PIN DA[7]
		DIRECTION INPUT ;
		USE SIGNAL ;
		PORT
			LAYER M3 ;
			RECT 57.205 0.000 57.525 0.440 ;
			LAYER M1 ;
			RECT 57.205 0.000 57.525 0.440 ;
			LAYER M2 ;
			RECT 57.205 0.000 57.525 0.440 ;
		END
	END DA[7]

	PIN DA[8]
		DIRECTION INPUT ;
		USE SIGNAL ;
		PORT
			LAYER M3 ;
			RECT 64.845 0.000 65.165 0.440 ;
			LAYER M2 ;
			RECT 64.845 0.000 65.165 0.440 ;
			LAYER M1 ;
			RECT 64.845 0.000 65.165 0.440 ;
		END
	END DA[8]

	PIN DA[9]
		DIRECTION INPUT ;
		USE SIGNAL ;
		PORT
			LAYER M2 ;
			RECT 72.485 0.000 72.805 0.440 ;
			LAYER M3 ;
			RECT 72.485 0.000 72.805 0.440 ;
			LAYER M1 ;
			RECT 72.485 0.000 72.805 0.440 ;
		END
	END DA[9]

	PIN DB[0]
		DIRECTION INPUT ;
		USE SIGNAL ;
		PORT
			LAYER M3 ;
			RECT 8.845 0.000 9.165 0.440 ;
			LAYER M1 ;
			RECT 8.845 0.000 9.165 0.440 ;
			LAYER M2 ;
			RECT 8.845 0.000 9.165 0.440 ;
		END
	END DB[0]

	PIN DB[10]
		DIRECTION INPUT ;
		USE SIGNAL ;
		PORT
			LAYER M1 ;
			RECT 85.245 0.000 85.565 0.440 ;
			LAYER M3 ;
			RECT 85.245 0.000 85.565 0.440 ;
			LAYER M2 ;
			RECT 85.245 0.000 85.565 0.440 ;
		END
	END DB[10]

	PIN DB[11]
		DIRECTION INPUT ;
		USE SIGNAL ;
		PORT
			LAYER M3 ;
			RECT 92.885 0.000 93.205 0.440 ;
			LAYER M1 ;
			RECT 92.885 0.000 93.205 0.440 ;
			LAYER M2 ;
			RECT 92.885 0.000 93.205 0.440 ;
		END
	END DB[11]

	PIN DB[12]
		DIRECTION INPUT ;
		USE SIGNAL ;
		PORT
			LAYER M1 ;
			RECT 100.525 0.000 100.845 0.440 ;
			LAYER M2 ;
			RECT 100.525 0.000 100.845 0.440 ;
			LAYER M3 ;
			RECT 100.525 0.000 100.845 0.440 ;
		END
	END DB[12]

	PIN DB[13]
		DIRECTION INPUT ;
		USE SIGNAL ;
		PORT
			LAYER M3 ;
			RECT 108.165 0.000 108.485 0.440 ;
			LAYER M1 ;
			RECT 108.165 0.000 108.485 0.440 ;
			LAYER M2 ;
			RECT 108.165 0.000 108.485 0.440 ;
		END
	END DB[13]

	PIN DB[14]
		DIRECTION INPUT ;
		USE SIGNAL ;
		PORT
			LAYER M2 ;
			RECT 115.805 0.000 116.125 0.440 ;
			LAYER M3 ;
			RECT 115.805 0.000 116.125 0.440 ;
			LAYER M1 ;
			RECT 115.805 0.000 116.125 0.440 ;
		END
	END DB[14]

	PIN DB[15]
		DIRECTION INPUT ;
		USE SIGNAL ;
		PORT
			LAYER M1 ;
			RECT 123.445 0.000 123.765 0.440 ;
			LAYER M3 ;
			RECT 123.445 0.000 123.765 0.440 ;
			LAYER M2 ;
			RECT 123.445 0.000 123.765 0.440 ;
		END
	END DB[15]

	PIN DB[16]
		DIRECTION INPUT ;
		USE SIGNAL ;
		PORT
			LAYER M3 ;
			RECT 188.345 0.000 188.665 0.440 ;
			LAYER M2 ;
			RECT 188.345 0.000 188.665 0.440 ;
			LAYER M1 ;
			RECT 188.345 0.000 188.665 0.440 ;
		END
	END DB[16]

	PIN DB[17]
		DIRECTION INPUT ;
		USE SIGNAL ;
		PORT
			LAYER M3 ;
			RECT 195.985 0.000 196.305 0.440 ;
			LAYER M1 ;
			RECT 195.985 0.000 196.305 0.440 ;
			LAYER M2 ;
			RECT 195.985 0.000 196.305 0.440 ;
		END
	END DB[17]

	PIN DB[18]
		DIRECTION INPUT ;
		USE SIGNAL ;
		PORT
			LAYER M2 ;
			RECT 203.625 0.000 203.945 0.440 ;
			LAYER M1 ;
			RECT 203.625 0.000 203.945 0.440 ;
			LAYER M3 ;
			RECT 203.625 0.000 203.945 0.440 ;
		END
	END DB[18]

	PIN DB[19]
		DIRECTION INPUT ;
		USE SIGNAL ;
		PORT
			LAYER M2 ;
			RECT 211.265 0.000 211.585 0.440 ;
			LAYER M3 ;
			RECT 211.265 0.000 211.585 0.440 ;
			LAYER M1 ;
			RECT 211.265 0.000 211.585 0.440 ;
		END
	END DB[19]

	PIN DB[1]
		DIRECTION INPUT ;
		USE SIGNAL ;
		PORT
			LAYER M1 ;
			RECT 16.485 0.000 16.805 0.440 ;
			LAYER M2 ;
			RECT 16.485 0.000 16.805 0.440 ;
			LAYER M3 ;
			RECT 16.485 0.000 16.805 0.440 ;
		END
	END DB[1]

	PIN DB[20]
		DIRECTION INPUT ;
		USE SIGNAL ;
		PORT
			LAYER M2 ;
			RECT 218.905 0.000 219.225 0.440 ;
			LAYER M3 ;
			RECT 218.905 0.000 219.225 0.440 ;
			LAYER M1 ;
			RECT 218.905 0.000 219.225 0.440 ;
		END
	END DB[20]

	PIN DB[21]
		DIRECTION INPUT ;
		USE SIGNAL ;
		PORT
			LAYER M2 ;
			RECT 226.545 0.000 226.865 0.440 ;
			LAYER M3 ;
			RECT 226.545 0.000 226.865 0.440 ;
			LAYER M1 ;
			RECT 226.545 0.000 226.865 0.440 ;
		END
	END DB[21]

	PIN DB[22]
		DIRECTION INPUT ;
		USE SIGNAL ;
		PORT
			LAYER M1 ;
			RECT 234.185 0.000 234.505 0.440 ;
			LAYER M2 ;
			RECT 234.185 0.000 234.505 0.440 ;
			LAYER M3 ;
			RECT 234.185 0.000 234.505 0.440 ;
		END
	END DB[22]

	PIN DB[23]
		DIRECTION INPUT ;
		USE SIGNAL ;
		PORT
			LAYER M2 ;
			RECT 241.825 0.000 242.145 0.440 ;
			LAYER M3 ;
			RECT 241.825 0.000 242.145 0.440 ;
			LAYER M1 ;
			RECT 241.825 0.000 242.145 0.440 ;
		END
	END DB[23]

	PIN DB[24]
		DIRECTION INPUT ;
		USE SIGNAL ;
		PORT
			LAYER M2 ;
			RECT 249.465 0.000 249.785 0.440 ;
			LAYER M3 ;
			RECT 249.465 0.000 249.785 0.440 ;
			LAYER M1 ;
			RECT 249.465 0.000 249.785 0.440 ;
		END
	END DB[24]

	PIN DB[25]
		DIRECTION INPUT ;
		USE SIGNAL ;
		PORT
			LAYER M3 ;
			RECT 257.105 0.000 257.425 0.440 ;
			LAYER M1 ;
			RECT 257.105 0.000 257.425 0.440 ;
			LAYER M2 ;
			RECT 257.105 0.000 257.425 0.440 ;
		END
	END DB[25]

	PIN DB[26]
		DIRECTION INPUT ;
		USE SIGNAL ;
		PORT
			LAYER M2 ;
			RECT 264.745 0.000 265.065 0.440 ;
			LAYER M1 ;
			RECT 264.745 0.000 265.065 0.440 ;
			LAYER M3 ;
			RECT 264.745 0.000 265.065 0.440 ;
		END
	END DB[26]

	PIN DB[27]
		DIRECTION INPUT ;
		USE SIGNAL ;
		PORT
			LAYER M3 ;
			RECT 272.385 0.000 272.705 0.440 ;
			LAYER M1 ;
			RECT 272.385 0.000 272.705 0.440 ;
			LAYER M2 ;
			RECT 272.385 0.000 272.705 0.440 ;
		END
	END DB[27]

	PIN DB[28]
		DIRECTION INPUT ;
		USE SIGNAL ;
		PORT
			LAYER M3 ;
			RECT 280.025 0.000 280.345 0.440 ;
			LAYER M2 ;
			RECT 280.025 0.000 280.345 0.440 ;
			LAYER M1 ;
			RECT 280.025 0.000 280.345 0.440 ;
		END
	END DB[28]

	PIN DB[29]
		DIRECTION INPUT ;
		USE SIGNAL ;
		PORT
			LAYER M1 ;
			RECT 287.665 0.000 287.985 0.440 ;
			LAYER M2 ;
			RECT 287.665 0.000 287.985 0.440 ;
			LAYER M3 ;
			RECT 287.665 0.000 287.985 0.440 ;
		END
	END DB[29]

	PIN DB[2]
		DIRECTION INPUT ;
		USE SIGNAL ;
		PORT
			LAYER M3 ;
			RECT 24.125 0.000 24.445 0.440 ;
			LAYER M2 ;
			RECT 24.125 0.000 24.445 0.440 ;
			LAYER M1 ;
			RECT 24.125 0.000 24.445 0.440 ;
		END
	END DB[2]

	PIN DB[30]
		DIRECTION INPUT ;
		USE SIGNAL ;
		PORT
			LAYER M2 ;
			RECT 295.305 0.000 295.625 0.440 ;
			LAYER M3 ;
			RECT 295.305 0.000 295.625 0.440 ;
			LAYER M1 ;
			RECT 295.305 0.000 295.625 0.440 ;
		END
	END DB[30]

	PIN DB[31]
		DIRECTION INPUT ;
		USE SIGNAL ;
		PORT
			LAYER M2 ;
			RECT 302.945 0.000 303.265 0.440 ;
			LAYER M1 ;
			RECT 302.945 0.000 303.265 0.440 ;
			LAYER M3 ;
			RECT 302.945 0.000 303.265 0.440 ;
		END
	END DB[31]

	PIN DB[3]
		DIRECTION INPUT ;
		USE SIGNAL ;
		PORT
			LAYER M1 ;
			RECT 31.765 0.000 32.085 0.440 ;
			LAYER M2 ;
			RECT 31.765 0.000 32.085 0.440 ;
			LAYER M3 ;
			RECT 31.765 0.000 32.085 0.440 ;
		END
	END DB[3]

	PIN DB[4]
		DIRECTION INPUT ;
		USE SIGNAL ;
		PORT
			LAYER M1 ;
			RECT 39.405 0.000 39.725 0.440 ;
			LAYER M3 ;
			RECT 39.405 0.000 39.725 0.440 ;
			LAYER M2 ;
			RECT 39.405 0.000 39.725 0.440 ;
		END
	END DB[4]

	PIN DB[5]
		DIRECTION INPUT ;
		USE SIGNAL ;
		PORT
			LAYER M1 ;
			RECT 47.045 0.000 47.365 0.440 ;
			LAYER M3 ;
			RECT 47.045 0.000 47.365 0.440 ;
			LAYER M2 ;
			RECT 47.045 0.000 47.365 0.440 ;
		END
	END DB[5]

	PIN DB[6]
		DIRECTION INPUT ;
		USE SIGNAL ;
		PORT
			LAYER M3 ;
			RECT 54.685 0.000 55.005 0.440 ;
			LAYER M1 ;
			RECT 54.685 0.000 55.005 0.440 ;
			LAYER M2 ;
			RECT 54.685 0.000 55.005 0.440 ;
		END
	END DB[6]

	PIN DB[7]
		DIRECTION INPUT ;
		USE SIGNAL ;
		PORT
			LAYER M3 ;
			RECT 62.325 0.000 62.645 0.440 ;
			LAYER M1 ;
			RECT 62.325 0.000 62.645 0.440 ;
			LAYER M2 ;
			RECT 62.325 0.000 62.645 0.440 ;
		END
	END DB[7]

	PIN DB[8]
		DIRECTION INPUT ;
		USE SIGNAL ;
		PORT
			LAYER M2 ;
			RECT 69.965 0.000 70.285 0.440 ;
			LAYER M1 ;
			RECT 69.965 0.000 70.285 0.440 ;
			LAYER M3 ;
			RECT 69.965 0.000 70.285 0.440 ;
		END
	END DB[8]

	PIN DB[9]
		DIRECTION INPUT ;
		USE SIGNAL ;
		PORT
			LAYER M3 ;
			RECT 77.605 0.000 77.925 0.440 ;
			LAYER M1 ;
			RECT 77.605 0.000 77.925 0.440 ;
			LAYER M2 ;
			RECT 77.605 0.000 77.925 0.440 ;
		END
	END DB[9]

	PIN QA[0]
		DIRECTION OUTPUT ;
		USE SIGNAL ;
		PORT
			LAYER M3 ;
			RECT 4.485 0.000 4.805 0.440 ;
			LAYER M1 ;
			RECT 4.485 0.000 4.805 0.440 ;
			LAYER M2 ;
			RECT 4.485 0.000 4.805 0.440 ;
		END
	END QA[0]

	PIN QA[10]
		DIRECTION OUTPUT ;
		USE SIGNAL ;
		PORT
			LAYER M2 ;
			RECT 80.885 0.000 81.205 0.440 ;
			LAYER M1 ;
			RECT 80.885 0.000 81.205 0.440 ;
			LAYER M3 ;
			RECT 80.885 0.000 81.205 0.440 ;
		END
	END QA[10]

	PIN QA[11]
		DIRECTION OUTPUT ;
		USE SIGNAL ;
		PORT
			LAYER M1 ;
			RECT 88.525 0.000 88.845 0.440 ;
			LAYER M2 ;
			RECT 88.525 0.000 88.845 0.440 ;
			LAYER M3 ;
			RECT 88.525 0.000 88.845 0.440 ;
		END
	END QA[11]

	PIN QA[12]
		DIRECTION OUTPUT ;
		USE SIGNAL ;
		PORT
			LAYER M3 ;
			RECT 96.165 0.000 96.485 0.440 ;
			LAYER M1 ;
			RECT 96.165 0.000 96.485 0.440 ;
			LAYER M2 ;
			RECT 96.165 0.000 96.485 0.440 ;
		END
	END QA[12]

	PIN QA[13]
		DIRECTION OUTPUT ;
		USE SIGNAL ;
		PORT
			LAYER M3 ;
			RECT 103.805 0.000 104.125 0.440 ;
			LAYER M1 ;
			RECT 103.805 0.000 104.125 0.440 ;
			LAYER M2 ;
			RECT 103.805 0.000 104.125 0.440 ;
		END
	END QA[13]

	PIN QA[14]
		DIRECTION OUTPUT ;
		USE SIGNAL ;
		PORT
			LAYER M3 ;
			RECT 111.445 0.000 111.765 0.440 ;
			LAYER M1 ;
			RECT 111.445 0.000 111.765 0.440 ;
			LAYER M2 ;
			RECT 111.445 0.000 111.765 0.440 ;
		END
	END QA[14]

	PIN QA[15]
		DIRECTION OUTPUT ;
		USE SIGNAL ;
		PORT
			LAYER M3 ;
			RECT 119.085 0.000 119.405 0.440 ;
			LAYER M2 ;
			RECT 119.085 0.000 119.405 0.440 ;
			LAYER M1 ;
			RECT 119.085 0.000 119.405 0.440 ;
		END
	END QA[15]

	PIN QA[16]
		DIRECTION OUTPUT ;
		USE SIGNAL ;
		PORT
			LAYER M2 ;
			RECT 183.985 0.000 184.305 0.440 ;
			LAYER M3 ;
			RECT 183.985 0.000 184.305 0.440 ;
			LAYER M1 ;
			RECT 183.985 0.000 184.305 0.440 ;
		END
	END QA[16]

	PIN QA[17]
		DIRECTION OUTPUT ;
		USE SIGNAL ;
		PORT
			LAYER M3 ;
			RECT 191.625 0.000 191.945 0.440 ;
			LAYER M1 ;
			RECT 191.625 0.000 191.945 0.440 ;
			LAYER M2 ;
			RECT 191.625 0.000 191.945 0.440 ;
		END
	END QA[17]

	PIN QA[18]
		DIRECTION OUTPUT ;
		USE SIGNAL ;
		PORT
			LAYER M2 ;
			RECT 199.265 0.000 199.585 0.440 ;
			LAYER M1 ;
			RECT 199.265 0.000 199.585 0.440 ;
			LAYER M3 ;
			RECT 199.265 0.000 199.585 0.440 ;
		END
	END QA[18]

	PIN QA[19]
		DIRECTION OUTPUT ;
		USE SIGNAL ;
		PORT
			LAYER M2 ;
			RECT 206.905 0.000 207.225 0.440 ;
			LAYER M3 ;
			RECT 206.905 0.000 207.225 0.440 ;
			LAYER M1 ;
			RECT 206.905 0.000 207.225 0.440 ;
		END
	END QA[19]

	PIN QA[1]
		DIRECTION OUTPUT ;
		USE SIGNAL ;
		PORT
			LAYER M3 ;
			RECT 12.125 0.000 12.445 0.440 ;
			LAYER M1 ;
			RECT 12.125 0.000 12.445 0.440 ;
			LAYER M2 ;
			RECT 12.125 0.000 12.445 0.440 ;
		END
	END QA[1]

	PIN QA[20]
		DIRECTION OUTPUT ;
		USE SIGNAL ;
		PORT
			LAYER M3 ;
			RECT 214.545 0.000 214.865 0.440 ;
			LAYER M1 ;
			RECT 214.545 0.000 214.865 0.440 ;
			LAYER M2 ;
			RECT 214.545 0.000 214.865 0.440 ;
		END
	END QA[20]

	PIN QA[21]
		DIRECTION OUTPUT ;
		USE SIGNAL ;
		PORT
			LAYER M2 ;
			RECT 222.185 0.000 222.505 0.440 ;
			LAYER M3 ;
			RECT 222.185 0.000 222.505 0.440 ;
			LAYER M1 ;
			RECT 222.185 0.000 222.505 0.440 ;
		END
	END QA[21]

	PIN QA[22]
		DIRECTION OUTPUT ;
		USE SIGNAL ;
		PORT
			LAYER M2 ;
			RECT 229.825 0.000 230.145 0.440 ;
			LAYER M3 ;
			RECT 229.825 0.000 230.145 0.440 ;
			LAYER M1 ;
			RECT 229.825 0.000 230.145 0.440 ;
		END
	END QA[22]

	PIN QA[23]
		DIRECTION OUTPUT ;
		USE SIGNAL ;
		PORT
			LAYER M2 ;
			RECT 237.465 0.000 237.785 0.440 ;
			LAYER M1 ;
			RECT 237.465 0.000 237.785 0.440 ;
			LAYER M3 ;
			RECT 237.465 0.000 237.785 0.440 ;
		END
	END QA[23]

	PIN QA[24]
		DIRECTION OUTPUT ;
		USE SIGNAL ;
		PORT
			LAYER M2 ;
			RECT 245.105 0.000 245.425 0.440 ;
			LAYER M3 ;
			RECT 245.105 0.000 245.425 0.440 ;
			LAYER M1 ;
			RECT 245.105 0.000 245.425 0.440 ;
		END
	END QA[24]

	PIN QA[25]
		DIRECTION OUTPUT ;
		USE SIGNAL ;
		PORT
			LAYER M2 ;
			RECT 252.745 0.000 253.065 0.440 ;
			LAYER M3 ;
			RECT 252.745 0.000 253.065 0.440 ;
			LAYER M1 ;
			RECT 252.745 0.000 253.065 0.440 ;
		END
	END QA[25]

	PIN QA[26]
		DIRECTION OUTPUT ;
		USE SIGNAL ;
		PORT
			LAYER M2 ;
			RECT 260.385 0.000 260.705 0.440 ;
			LAYER M3 ;
			RECT 260.385 0.000 260.705 0.440 ;
			LAYER M1 ;
			RECT 260.385 0.000 260.705 0.440 ;
		END
	END QA[26]

	PIN QA[27]
		DIRECTION OUTPUT ;
		USE SIGNAL ;
		PORT
			LAYER M1 ;
			RECT 268.025 0.000 268.345 0.440 ;
			LAYER M3 ;
			RECT 268.025 0.000 268.345 0.440 ;
			LAYER M2 ;
			RECT 268.025 0.000 268.345 0.440 ;
		END
	END QA[27]

	PIN QA[28]
		DIRECTION OUTPUT ;
		USE SIGNAL ;
		PORT
			LAYER M3 ;
			RECT 275.665 0.000 275.985 0.440 ;
			LAYER M1 ;
			RECT 275.665 0.000 275.985 0.440 ;
			LAYER M2 ;
			RECT 275.665 0.000 275.985 0.440 ;
		END
	END QA[28]

	PIN QA[29]
		DIRECTION OUTPUT ;
		USE SIGNAL ;
		PORT
			LAYER M3 ;
			RECT 283.305 0.000 283.625 0.440 ;
			LAYER M1 ;
			RECT 283.305 0.000 283.625 0.440 ;
			LAYER M2 ;
			RECT 283.305 0.000 283.625 0.440 ;
		END
	END QA[29]

	PIN QA[2]
		DIRECTION OUTPUT ;
		USE SIGNAL ;
		PORT
			LAYER M2 ;
			RECT 19.765 0.000 20.085 0.440 ;
			LAYER M3 ;
			RECT 19.765 0.000 20.085 0.440 ;
			LAYER M1 ;
			RECT 19.765 0.000 20.085 0.440 ;
		END
	END QA[2]

	PIN QA[30]
		DIRECTION OUTPUT ;
		USE SIGNAL ;
		PORT
			LAYER M3 ;
			RECT 290.945 0.000 291.265 0.440 ;
			LAYER M1 ;
			RECT 290.945 0.000 291.265 0.440 ;
			LAYER M2 ;
			RECT 290.945 0.000 291.265 0.440 ;
		END
	END QA[30]

	PIN QA[31]
		DIRECTION OUTPUT ;
		USE SIGNAL ;
		PORT
			LAYER M3 ;
			RECT 298.585 0.000 298.905 0.440 ;
			LAYER M2 ;
			RECT 298.585 0.000 298.905 0.440 ;
			LAYER M1 ;
			RECT 298.585 0.000 298.905 0.440 ;
		END
	END QA[31]

	PIN QA[3]
		DIRECTION OUTPUT ;
		USE SIGNAL ;
		PORT
			LAYER M2 ;
			RECT 27.405 0.000 27.725 0.440 ;
			LAYER M3 ;
			RECT 27.405 0.000 27.725 0.440 ;
			LAYER M1 ;
			RECT 27.405 0.000 27.725 0.440 ;
		END
	END QA[3]

	PIN QA[4]
		DIRECTION OUTPUT ;
		USE SIGNAL ;
		PORT
			LAYER M3 ;
			RECT 35.045 0.000 35.365 0.440 ;
			LAYER M1 ;
			RECT 35.045 0.000 35.365 0.440 ;
			LAYER M2 ;
			RECT 35.045 0.000 35.365 0.440 ;
		END
	END QA[4]

	PIN QA[5]
		DIRECTION OUTPUT ;
		USE SIGNAL ;
		PORT
			LAYER M2 ;
			RECT 42.685 0.000 43.005 0.440 ;
			LAYER M3 ;
			RECT 42.685 0.000 43.005 0.440 ;
			LAYER M1 ;
			RECT 42.685 0.000 43.005 0.440 ;
		END
	END QA[5]

	PIN QA[6]
		DIRECTION OUTPUT ;
		USE SIGNAL ;
		PORT
			LAYER M2 ;
			RECT 50.325 0.000 50.645 0.440 ;
			LAYER M3 ;
			RECT 50.325 0.000 50.645 0.440 ;
			LAYER M1 ;
			RECT 50.325 0.000 50.645 0.440 ;
		END
	END QA[6]

	PIN QA[7]
		DIRECTION OUTPUT ;
		USE SIGNAL ;
		PORT
			LAYER M2 ;
			RECT 57.965 0.000 58.285 0.440 ;
			LAYER M3 ;
			RECT 57.965 0.000 58.285 0.440 ;
			LAYER M1 ;
			RECT 57.965 0.000 58.285 0.440 ;
		END
	END QA[7]

	PIN QA[8]
		DIRECTION OUTPUT ;
		USE SIGNAL ;
		PORT
			LAYER M2 ;
			RECT 65.605 0.000 65.925 0.440 ;
			LAYER M3 ;
			RECT 65.605 0.000 65.925 0.440 ;
			LAYER M1 ;
			RECT 65.605 0.000 65.925 0.440 ;
		END
	END QA[8]

	PIN QA[9]
		DIRECTION OUTPUT ;
		USE SIGNAL ;
		PORT
			LAYER M3 ;
			RECT 73.245 0.000 73.565 0.440 ;
			LAYER M1 ;
			RECT 73.245 0.000 73.565 0.440 ;
			LAYER M2 ;
			RECT 73.245 0.000 73.565 0.440 ;
		END
	END QA[9]

	PIN QB[0]
		DIRECTION OUTPUT ;
		USE SIGNAL ;
		PORT
			LAYER M2 ;
			RECT 8.085 0.000 8.405 0.440 ;
			LAYER M3 ;
			RECT 8.085 0.000 8.405 0.440 ;
			LAYER M1 ;
			RECT 8.085 0.000 8.405 0.440 ;
		END
	END QB[0]

	PIN QB[10]
		DIRECTION OUTPUT ;
		USE SIGNAL ;
		PORT
			LAYER M2 ;
			RECT 84.485 0.000 84.805 0.440 ;
			LAYER M3 ;
			RECT 84.485 0.000 84.805 0.440 ;
			LAYER M1 ;
			RECT 84.485 0.000 84.805 0.440 ;
		END
	END QB[10]

	PIN QB[11]
		DIRECTION OUTPUT ;
		USE SIGNAL ;
		PORT
			LAYER M1 ;
			RECT 92.125 0.000 92.445 0.440 ;
			LAYER M2 ;
			RECT 92.125 0.000 92.445 0.440 ;
			LAYER M3 ;
			RECT 92.125 0.000 92.445 0.440 ;
		END
	END QB[11]

	PIN QB[12]
		DIRECTION OUTPUT ;
		USE SIGNAL ;
		PORT
			LAYER M2 ;
			RECT 99.765 0.000 100.085 0.440 ;
			LAYER M3 ;
			RECT 99.765 0.000 100.085 0.440 ;
			LAYER M1 ;
			RECT 99.765 0.000 100.085 0.440 ;
		END
	END QB[12]

	PIN QB[13]
		DIRECTION OUTPUT ;
		USE SIGNAL ;
		PORT
			LAYER M2 ;
			RECT 107.405 0.000 107.725 0.440 ;
			LAYER M3 ;
			RECT 107.405 0.000 107.725 0.440 ;
			LAYER M1 ;
			RECT 107.405 0.000 107.725 0.440 ;
		END
	END QB[13]

	PIN QB[14]
		DIRECTION OUTPUT ;
		USE SIGNAL ;
		PORT
			LAYER M2 ;
			RECT 115.045 0.000 115.365 0.440 ;
			LAYER M3 ;
			RECT 115.045 0.000 115.365 0.440 ;
			LAYER M1 ;
			RECT 115.045 0.000 115.365 0.440 ;
		END
	END QB[14]

	PIN QB[15]
		DIRECTION OUTPUT ;
		USE SIGNAL ;
		PORT
			LAYER M2 ;
			RECT 122.685 0.000 123.005 0.440 ;
			LAYER M3 ;
			RECT 122.685 0.000 123.005 0.440 ;
			LAYER M1 ;
			RECT 122.685 0.000 123.005 0.440 ;
		END
	END QB[15]

	PIN QB[16]
		DIRECTION OUTPUT ;
		USE SIGNAL ;
		PORT
			LAYER M2 ;
			RECT 187.585 0.000 187.905 0.440 ;
			LAYER M3 ;
			RECT 187.585 0.000 187.905 0.440 ;
			LAYER M1 ;
			RECT 187.585 0.000 187.905 0.440 ;
		END
	END QB[16]

	PIN QB[17]
		DIRECTION OUTPUT ;
		USE SIGNAL ;
		PORT
			LAYER M2 ;
			RECT 195.225 0.000 195.545 0.440 ;
			LAYER M3 ;
			RECT 195.225 0.000 195.545 0.440 ;
			LAYER M1 ;
			RECT 195.225 0.000 195.545 0.440 ;
		END
	END QB[17]

	PIN QB[18]
		DIRECTION OUTPUT ;
		USE SIGNAL ;
		PORT
			LAYER M2 ;
			RECT 202.865 0.000 203.185 0.440 ;
			LAYER M3 ;
			RECT 202.865 0.000 203.185 0.440 ;
			LAYER M1 ;
			RECT 202.865 0.000 203.185 0.440 ;
		END
	END QB[18]

	PIN QB[19]
		DIRECTION OUTPUT ;
		USE SIGNAL ;
		PORT
			LAYER M2 ;
			RECT 210.505 0.000 210.825 0.440 ;
			LAYER M3 ;
			RECT 210.505 0.000 210.825 0.440 ;
			LAYER M1 ;
			RECT 210.505 0.000 210.825 0.440 ;
		END
	END QB[19]

	PIN QB[1]
		DIRECTION OUTPUT ;
		USE SIGNAL ;
		PORT
			LAYER M2 ;
			RECT 15.725 0.000 16.045 0.440 ;
			LAYER M3 ;
			RECT 15.725 0.000 16.045 0.440 ;
			LAYER M1 ;
			RECT 15.725 0.000 16.045 0.440 ;
		END
	END QB[1]

	PIN QB[20]
		DIRECTION OUTPUT ;
		USE SIGNAL ;
		PORT
			LAYER M3 ;
			RECT 218.145 0.000 218.465 0.440 ;
			LAYER M1 ;
			RECT 218.145 0.000 218.465 0.440 ;
			LAYER M2 ;
			RECT 218.145 0.000 218.465 0.440 ;
		END
	END QB[20]

	PIN QB[21]
		DIRECTION OUTPUT ;
		USE SIGNAL ;
		PORT
			LAYER M1 ;
			RECT 225.785 0.000 226.105 0.440 ;
			LAYER M2 ;
			RECT 225.785 0.000 226.105 0.440 ;
			LAYER M3 ;
			RECT 225.785 0.000 226.105 0.440 ;
		END
	END QB[21]

	PIN QB[22]
		DIRECTION OUTPUT ;
		USE SIGNAL ;
		PORT
			LAYER M2 ;
			RECT 233.425 0.000 233.745 0.440 ;
			LAYER M3 ;
			RECT 233.425 0.000 233.745 0.440 ;
			LAYER M1 ;
			RECT 233.425 0.000 233.745 0.440 ;
		END
	END QB[22]

	PIN QB[23]
		DIRECTION OUTPUT ;
		USE SIGNAL ;
		PORT
			LAYER M2 ;
			RECT 241.065 0.000 241.385 0.440 ;
			LAYER M3 ;
			RECT 241.065 0.000 241.385 0.440 ;
			LAYER M1 ;
			RECT 241.065 0.000 241.385 0.440 ;
		END
	END QB[23]

	PIN QB[24]
		DIRECTION OUTPUT ;
		USE SIGNAL ;
		PORT
			LAYER M2 ;
			RECT 248.705 0.000 249.025 0.440 ;
			LAYER M3 ;
			RECT 248.705 0.000 249.025 0.440 ;
			LAYER M1 ;
			RECT 248.705 0.000 249.025 0.440 ;
		END
	END QB[24]

	PIN QB[25]
		DIRECTION OUTPUT ;
		USE SIGNAL ;
		PORT
			LAYER M3 ;
			RECT 256.345 0.000 256.665 0.440 ;
			LAYER M1 ;
			RECT 256.345 0.000 256.665 0.440 ;
			LAYER M2 ;
			RECT 256.345 0.000 256.665 0.440 ;
		END
	END QB[25]

	PIN QB[26]
		DIRECTION OUTPUT ;
		USE SIGNAL ;
		PORT
			LAYER M2 ;
			RECT 263.985 0.000 264.305 0.440 ;
			LAYER M3 ;
			RECT 263.985 0.000 264.305 0.440 ;
			LAYER M1 ;
			RECT 263.985 0.000 264.305 0.440 ;
		END
	END QB[26]

	PIN QB[27]
		DIRECTION OUTPUT ;
		USE SIGNAL ;
		PORT
			LAYER M2 ;
			RECT 271.625 0.000 271.945 0.440 ;
			LAYER M1 ;
			RECT 271.625 0.000 271.945 0.440 ;
			LAYER M3 ;
			RECT 271.625 0.000 271.945 0.440 ;
		END
	END QB[27]

	PIN QB[28]
		DIRECTION OUTPUT ;
		USE SIGNAL ;
		PORT
			LAYER M2 ;
			RECT 279.265 0.000 279.585 0.440 ;
			LAYER M3 ;
			RECT 279.265 0.000 279.585 0.440 ;
			LAYER M1 ;
			RECT 279.265 0.000 279.585 0.440 ;
		END
	END QB[28]

	PIN QB[29]
		DIRECTION OUTPUT ;
		USE SIGNAL ;
		PORT
			LAYER M2 ;
			RECT 286.905 0.000 287.225 0.440 ;
			LAYER M3 ;
			RECT 286.905 0.000 287.225 0.440 ;
			LAYER M1 ;
			RECT 286.905 0.000 287.225 0.440 ;
		END
	END QB[29]

	PIN QB[2]
		DIRECTION OUTPUT ;
		USE SIGNAL ;
		PORT
			LAYER M3 ;
			RECT 23.365 0.000 23.685 0.440 ;
			LAYER M1 ;
			RECT 23.365 0.000 23.685 0.440 ;
			LAYER M2 ;
			RECT 23.365 0.000 23.685 0.440 ;
		END
	END QB[2]

	PIN QB[30]
		DIRECTION OUTPUT ;
		USE SIGNAL ;
		PORT
			LAYER M2 ;
			RECT 294.545 0.000 294.865 0.440 ;
			LAYER M1 ;
			RECT 294.545 0.000 294.865 0.440 ;
			LAYER M3 ;
			RECT 294.545 0.000 294.865 0.440 ;
		END
	END QB[30]

	PIN QB[31]
		DIRECTION OUTPUT ;
		USE SIGNAL ;
		PORT
			LAYER M2 ;
			RECT 302.185 0.000 302.505 0.440 ;
			LAYER M3 ;
			RECT 302.185 0.000 302.505 0.440 ;
			LAYER M1 ;
			RECT 302.185 0.000 302.505 0.440 ;
		END
	END QB[31]

	PIN QB[3]
		DIRECTION OUTPUT ;
		USE SIGNAL ;
		PORT
			LAYER M2 ;
			RECT 31.005 0.000 31.325 0.440 ;
			LAYER M1 ;
			RECT 31.005 0.000 31.325 0.440 ;
			LAYER M3 ;
			RECT 31.005 0.000 31.325 0.440 ;
		END
	END QB[3]

	PIN QB[4]
		DIRECTION OUTPUT ;
		USE SIGNAL ;
		PORT
			LAYER M3 ;
			RECT 38.645 0.000 38.965 0.440 ;
			LAYER M1 ;
			RECT 38.645 0.000 38.965 0.440 ;
			LAYER M2 ;
			RECT 38.645 0.000 38.965 0.440 ;
		END
	END QB[4]

	PIN QB[5]
		DIRECTION OUTPUT ;
		USE SIGNAL ;
		PORT
			LAYER M1 ;
			RECT 46.285 0.000 46.605 0.440 ;
			LAYER M2 ;
			RECT 46.285 0.000 46.605 0.440 ;
			LAYER M3 ;
			RECT 46.285 0.000 46.605 0.440 ;
		END
	END QB[5]

	PIN QB[6]
		DIRECTION OUTPUT ;
		USE SIGNAL ;
		PORT
			LAYER M2 ;
			RECT 53.925 0.000 54.245 0.440 ;
			LAYER M3 ;
			RECT 53.925 0.000 54.245 0.440 ;
			LAYER M1 ;
			RECT 53.925 0.000 54.245 0.440 ;
		END
	END QB[6]

	PIN QB[7]
		DIRECTION OUTPUT ;
		USE SIGNAL ;
		PORT
			LAYER M2 ;
			RECT 61.565 0.000 61.885 0.440 ;
			LAYER M1 ;
			RECT 61.565 0.000 61.885 0.440 ;
			LAYER M3 ;
			RECT 61.565 0.000 61.885 0.440 ;
		END
	END QB[7]

	PIN QB[8]
		DIRECTION OUTPUT ;
		USE SIGNAL ;
		PORT
			LAYER M3 ;
			RECT 69.205 0.000 69.525 0.440 ;
			LAYER M1 ;
			RECT 69.205 0.000 69.525 0.440 ;
			LAYER M2 ;
			RECT 69.205 0.000 69.525 0.440 ;
		END
	END QB[8]

	PIN QB[9]
		DIRECTION OUTPUT ;
		USE SIGNAL ;
		PORT
			LAYER M3 ;
			RECT 76.845 0.000 77.165 0.440 ;
			LAYER M1 ;
			RECT 76.845 0.000 77.165 0.440 ;
			LAYER M2 ;
			RECT 76.845 0.000 77.165 0.440 ;
		END
	END QB[9]

	PIN VDD
		DIRECTION INOUT ;
		USE POWER ;
		PORT
			LAYER M5 ;
			RECT 0.000 34.705 132.695 37.205 ;
			LAYER M5 ;
			RECT 0.000 174.875 132.695 177.375 ;
			LAYER M5 ;
			RECT 174.295 34.705 306.990 37.205 ;
			LAYER M5 ;
			RECT 128.695 37.205 132.695 174.875 ;
			LAYER M5 ;
			RECT 174.295 37.205 178.295 174.875 ;
			LAYER M5 ;
			RECT 174.295 174.875 306.990 177.375 ;
		END
	END VDD

	PIN VSS
		DIRECTION INOUT ;
		USE GROUND ;
		PORT
			LAYER M5 ;
			RECT 0.000 31.605 137.295 34.105 ;
			LAYER M5 ;
			RECT 0.000 177.975 137.295 180.475 ;
			LAYER M5 ;
			RECT 169.695 31.605 306.990 34.105 ;
			LAYER M5 ;
			RECT 133.295 34.105 137.295 177.975 ;
			LAYER M5 ;
			RECT 169.695 34.105 173.695 177.975 ;
			LAYER M5 ;
			RECT 169.695 177.975 306.990 180.475 ;
		END
	END VSS

	PIN WEBA
		DIRECTION INPUT ;
		USE SIGNAL ;
		PORT
			LAYER M2 ;
			RECT 143.715 0.000 144.035 0.440 ;
			LAYER M3 ;
			RECT 143.715 0.000 144.035 0.440 ;
			LAYER M1 ;
			RECT 143.715 0.000 144.035 0.440 ;
		END
	END WEBA

	PIN WEBB
		DIRECTION INPUT ;
		USE SIGNAL ;
		PORT
			LAYER M3 ;
			RECT 162.955 0.000 163.275 0.440 ;
			LAYER M2 ;
			RECT 162.955 0.000 163.275 0.440 ;
			LAYER M1 ;
			RECT 162.955 0.000 163.275 0.440 ;
		END
	END WEBB
	OBS
		# Promoted blockages
		LAYER M2 ;
		RECT 260.065 0.000 260.265 0.440 ;
		LAYER M2 ;
		RECT 256.785 0.000 256.985 0.440 ;
		LAYER M1 ;
		RECT 256.775 0.000 256.995 0.440 ;
		LAYER M2 ;
		RECT 257.545 0.000 259.505 0.440 ;
		LAYER M3 ;
		RECT 257.545 0.000 259.505 0.440 ;
		LAYER M3 ;
		RECT 253.945 0.000 255.465 0.440 ;
		LAYER M1 ;
		RECT 253.935 0.000 255.475 0.440 ;
		LAYER M3 ;
		RECT 253.185 0.000 253.385 0.440 ;
		LAYER M3 ;
		RECT 252.425 0.000 252.625 0.440 ;
		LAYER M2 ;
		RECT 253.945 0.000 255.465 0.440 ;
		LAYER M3 ;
		RECT 256.025 0.000 256.225 0.440 ;
		LAYER M2 ;
		RECT 249.145 0.000 249.345 0.440 ;
		LAYER M1 ;
		RECT 249.135 0.000 249.355 0.440 ;
		LAYER M2 ;
		RECT 248.385 0.000 248.585 0.440 ;
		LAYER M1 ;
		RECT 248.375 0.000 248.595 0.440 ;
		LAYER M1 ;
		RECT 249.895 0.000 251.875 0.440 ;
		LAYER M2 ;
		RECT 260.825 0.000 261.025 0.440 ;
		LAYER M1 ;
		RECT 260.815 0.000 261.035 0.440 ;
		LAYER M3 ;
		RECT 261.585 0.000 263.105 0.440 ;
		LAYER M1 ;
		RECT 264.415 0.000 264.635 0.440 ;
		LAYER M2 ;
		RECT 267.705 0.000 267.905 0.440 ;
		LAYER M3 ;
		RECT 267.705 0.000 267.905 0.440 ;
		LAYER M1 ;
		RECT 267.695 0.000 267.915 0.440 ;
		LAYER M2 ;
		RECT 268.465 0.000 268.665 0.440 ;
		LAYER M3 ;
		RECT 268.465 0.000 268.665 0.440 ;
		LAYER M1 ;
		RECT 268.455 0.000 268.675 0.440 ;
		LAYER M2 ;
		RECT 265.185 0.000 267.145 0.440 ;
		LAYER M1 ;
		RECT 265.175 0.000 267.155 0.440 ;
		LAYER M2 ;
		RECT 264.425 0.000 264.625 0.440 ;
		LAYER M3 ;
		RECT 265.185 0.000 267.145 0.440 ;
		LAYER M1 ;
		RECT 269.215 0.000 270.755 0.440 ;
		LAYER M2 ;
		RECT 272.065 0.000 272.265 0.440 ;
		LAYER M3 ;
		RECT 272.065 0.000 272.265 0.440 ;
		LAYER M1 ;
		RECT 272.055 0.000 272.275 0.440 ;
		LAYER M2 ;
		RECT 272.825 0.000 274.785 0.440 ;
		LAYER M3 ;
		RECT 272.825 0.000 274.785 0.440 ;
		LAYER M2 ;
		RECT 271.305 0.000 271.505 0.440 ;
		LAYER M1 ;
		RECT 272.815 0.000 274.795 0.440 ;
		LAYER M3 ;
		RECT 275.345 0.000 275.545 0.440 ;
		LAYER M3 ;
		RECT 271.305 0.000 271.505 0.440 ;
		LAYER M3 ;
		RECT 298.265 0.000 298.465 0.440 ;
		LAYER M2 ;
		RECT 295.745 0.000 297.705 0.440 ;
		LAYER M1 ;
		RECT 295.735 0.000 297.715 0.440 ;
		LAYER M1 ;
		RECT 294.975 0.000 295.195 0.440 ;
		LAYER M2 ;
		RECT 294.985 0.000 295.185 0.440 ;
		LAYER M2 ;
		RECT 298.265 0.000 298.465 0.440 ;
		LAYER M2 ;
		RECT 294.225 0.000 294.425 0.440 ;
		LAYER M1 ;
		RECT 294.215 0.000 294.435 0.440 ;
		LAYER M1 ;
		RECT 290.615 0.000 290.835 0.440 ;
		LAYER M3 ;
		RECT 288.105 0.000 290.065 0.440 ;
		LAYER M2 ;
		RECT 292.145 0.000 293.665 0.440 ;
		LAYER M2 ;
		RECT 290.625 0.000 290.825 0.440 ;
		LAYER M1 ;
		RECT 288.095 0.000 290.075 0.440 ;
		LAYER M3 ;
		RECT 287.345 0.000 287.545 0.440 ;
		LAYER M1 ;
		RECT 287.335 0.000 287.555 0.440 ;
		LAYER M2 ;
		RECT 287.345 0.000 287.545 0.440 ;
		LAYER M2 ;
		RECT 288.105 0.000 290.065 0.440 ;
		LAYER M3 ;
		RECT 291.385 0.000 291.585 0.440 ;
		LAYER M2 ;
		RECT 291.385 0.000 291.585 0.440 ;
		LAYER M1 ;
		RECT 291.375 0.000 291.595 0.440 ;
		LAYER M3 ;
		RECT 292.145 0.000 293.665 0.440 ;
		LAYER M1 ;
		RECT 284.495 0.000 286.035 0.440 ;
		LAYER M2 ;
		RECT 279.705 0.000 279.905 0.440 ;
		LAYER M3 ;
		RECT 280.465 0.000 282.425 0.440 ;
		LAYER M2 ;
		RECT 283.745 0.000 283.945 0.440 ;
		LAYER M3 ;
		RECT 283.745 0.000 283.945 0.440 ;
		LAYER M1 ;
		RECT 283.735 0.000 283.955 0.440 ;
		LAYER M2 ;
		RECT 282.985 0.000 283.185 0.440 ;
		LAYER M2 ;
		RECT 276.105 0.000 276.305 0.440 ;
		LAYER M3 ;
		RECT 276.105 0.000 276.305 0.440 ;
		LAYER M1 ;
		RECT 286.575 0.000 286.795 0.440 ;
		LAYER M3 ;
		RECT 276.865 0.000 278.385 0.440 ;
		LAYER M3 ;
		RECT 278.945 0.000 279.145 0.440 ;
		LAYER M3 ;
		RECT 279.705 0.000 279.905 0.440 ;
		LAYER M3 ;
		RECT 295.745 0.000 297.705 0.440 ;
		LAYER M2 ;
		RECT 280.465 0.000 282.425 0.440 ;
		LAYER M3 ;
		RECT 214.985 0.000 215.185 0.440 ;
		LAYER M1 ;
		RECT 214.975 0.000 215.195 0.440 ;
		LAYER M2 ;
		RECT 214.225 0.000 214.425 0.440 ;
		LAYER M1 ;
		RECT 214.215 0.000 214.435 0.440 ;
		LAYER M3 ;
		RECT 214.225 0.000 214.425 0.440 ;
		LAYER M2 ;
		RECT 214.985 0.000 215.185 0.440 ;
		LAYER M2 ;
		RECT 215.745 0.000 217.265 0.440 ;
		LAYER M1 ;
		RECT 215.735 0.000 217.275 0.440 ;
		LAYER M1 ;
		RECT 211.695 0.000 213.675 0.440 ;
		LAYER M2 ;
		RECT 207.345 0.000 207.545 0.440 ;
		LAYER M3 ;
		RECT 207.345 0.000 207.545 0.440 ;
		LAYER M1 ;
		RECT 210.175 0.000 210.395 0.440 ;
		LAYER M3 ;
		RECT 210.185 0.000 210.385 0.440 ;
		LAYER M2 ;
		RECT 208.105 0.000 209.625 0.440 ;
		LAYER M1 ;
		RECT 210.935 0.000 211.155 0.440 ;
		LAYER M2 ;
		RECT 210.945 0.000 211.145 0.440 ;
		LAYER M2 ;
		RECT 211.705 0.000 213.665 0.440 ;
		LAYER M3 ;
		RECT 211.705 0.000 213.665 0.440 ;
		LAYER M3 ;
		RECT 210.945 0.000 211.145 0.440 ;
		LAYER M3 ;
		RECT 246.305 0.000 247.825 0.440 ;
		LAYER M3 ;
		RECT 248.385 0.000 248.585 0.440 ;
		LAYER M2 ;
		RECT 249.905 0.000 251.865 0.440 ;
		LAYER M3 ;
		RECT 249.905 0.000 251.865 0.440 ;
		LAYER M3 ;
		RECT 249.145 0.000 249.345 0.440 ;
		LAYER M2 ;
		RECT 246.305 0.000 247.825 0.440 ;
		LAYER M1 ;
		RECT 245.535 0.000 245.755 0.440 ;
		LAYER M1 ;
		RECT 271.295 0.000 271.515 0.440 ;
		LAYER M2 ;
		RECT 269.225 0.000 270.745 0.440 ;
		LAYER M3 ;
		RECT 269.225 0.000 270.745 0.440 ;
		LAYER M1 ;
		RECT 246.295 0.000 247.835 0.440 ;
		LAYER M1 ;
		RECT 257.535 0.000 259.515 0.440 ;
		LAYER M3 ;
		RECT 260.065 0.000 260.265 0.440 ;
		LAYER M3 ;
		RECT 256.785 0.000 256.985 0.440 ;
		LAYER M2 ;
		RECT 222.625 0.000 222.825 0.440 ;
		LAYER M2 ;
		RECT 221.865 0.000 222.065 0.440 ;
		LAYER M3 ;
		RECT 221.865 0.000 222.065 0.440 ;
		LAYER M1 ;
		RECT 219.335 0.000 221.315 0.440 ;
		LAYER M1 ;
		RECT 217.815 0.000 218.035 0.440 ;
		LAYER M2 ;
		RECT 217.825 0.000 218.025 0.440 ;
		LAYER M2 ;
		RECT 218.585 0.000 218.785 0.440 ;
		LAYER M1 ;
		RECT 218.575 0.000 218.795 0.440 ;
		LAYER M3 ;
		RECT 218.585 0.000 218.785 0.440 ;
		LAYER M3 ;
		RECT 217.825 0.000 218.025 0.440 ;
		LAYER M1 ;
		RECT 240.735 0.000 240.955 0.440 ;
		LAYER M2 ;
		RECT 241.505 0.000 241.705 0.440 ;
		LAYER M1 ;
		RECT 241.495 0.000 241.715 0.440 ;
		LAYER M2 ;
		RECT 238.665 0.000 240.185 0.440 ;
		LAYER M3 ;
		RECT 241.505 0.000 241.705 0.440 ;
		LAYER M1 ;
		RECT 299.015 0.000 299.235 0.440 ;
		LAYER M1 ;
		RECT 298.255 0.000 298.475 0.440 ;
		LAYER M3 ;
		RECT 302.625 0.000 302.825 0.440 ;
		LAYER M1 ;
		RECT 299.775 0.000 301.315 0.440 ;
		LAYER M3 ;
		RECT 299.025 0.000 299.225 0.440 ;
		LAYER M2 ;
		RECT 299.025 0.000 299.225 0.440 ;
		LAYER M2 ;
		RECT 299.785 0.000 301.305 0.440 ;
		LAYER M3 ;
		RECT 299.785 0.000 301.305 0.440 ;
		LAYER M1 ;
		RECT 301.855 0.000 302.075 0.440 ;
		LAYER M2 ;
		RECT 302.625 0.000 302.825 0.440 ;
		LAYER M2 ;
		RECT 301.865 0.000 302.065 0.440 ;
		LAYER M3 ;
		RECT 301.865 0.000 302.065 0.440 ;
		LAYER M1 ;
		RECT 207.335 0.000 207.555 0.440 ;
		LAYER M3 ;
		RECT 208.105 0.000 209.625 0.440 ;
		LAYER M1 ;
		RECT 208.095 0.000 209.635 0.440 ;
		LAYER M2 ;
		RECT 210.185 0.000 210.385 0.440 ;
		LAYER M2 ;
		RECT 263.665 0.000 263.865 0.440 ;
		LAYER M1 ;
		RECT 263.655 0.000 263.875 0.440 ;
		LAYER M3 ;
		RECT 264.425 0.000 264.625 0.440 ;
		LAYER M2 ;
		RECT 261.585 0.000 263.105 0.440 ;
		LAYER M3 ;
		RECT 263.665 0.000 263.865 0.440 ;
		LAYER M1 ;
		RECT 261.575 0.000 263.115 0.440 ;
		LAYER M1 ;
		RECT 260.055 0.000 260.275 0.440 ;
		LAYER M3 ;
		RECT 260.825 0.000 261.025 0.440 ;
		LAYER M2 ;
		RECT 244.785 0.000 244.985 0.440 ;
		LAYER M1 ;
		RECT 252.415 0.000 252.635 0.440 ;
		LAYER M2 ;
		RECT 253.185 0.000 253.385 0.440 ;
		LAYER M1 ;
		RECT 253.175 0.000 253.395 0.440 ;
		LAYER M2 ;
		RECT 256.025 0.000 256.225 0.440 ;
		LAYER M1 ;
		RECT 256.015 0.000 256.235 0.440 ;
		LAYER M2 ;
		RECT 206.585 0.000 206.785 0.440 ;
		LAYER M3 ;
		RECT 199.705 0.000 199.905 0.440 ;
		LAYER M1 ;
		RECT 199.695 0.000 199.915 0.440 ;
		LAYER M3 ;
		RECT 206.585 0.000 206.785 0.440 ;
		LAYER M1 ;
		RECT 204.055 0.000 206.035 0.440 ;
		LAYER M3 ;
		RECT 204.065 0.000 206.025 0.440 ;
		LAYER M2 ;
		RECT 199.705 0.000 199.905 0.440 ;
		LAYER M1 ;
		RECT 244.775 0.000 244.995 0.440 ;
		LAYER M2 ;
		RECT 245.545 0.000 245.745 0.440 ;
		LAYER M3 ;
		RECT 245.545 0.000 245.745 0.440 ;
		LAYER M2 ;
		RECT 252.425 0.000 252.625 0.440 ;
		LAYER M3 ;
		RECT 244.785 0.000 244.985 0.440 ;
		LAYER M1 ;
		RECT 203.295 0.000 203.515 0.440 ;
		LAYER M2 ;
		RECT 202.545 0.000 202.745 0.440 ;
		LAYER M2 ;
		RECT 200.465 0.000 201.985 0.440 ;
		LAYER M1 ;
		RECT 200.455 0.000 201.995 0.440 ;
		LAYER M3 ;
		RECT 203.305 0.000 203.505 0.440 ;
		LAYER M1 ;
		RECT 196.415 0.000 198.395 0.440 ;
		LAYER M2 ;
		RECT 196.425 0.000 198.385 0.440 ;
		LAYER M2 ;
		RECT 198.945 0.000 199.145 0.440 ;
		LAYER M3 ;
		RECT 198.945 0.000 199.145 0.440 ;
		LAYER M1 ;
		RECT 198.935 0.000 199.155 0.440 ;
		LAYER M3 ;
		RECT 196.425 0.000 198.385 0.440 ;
		LAYER M3 ;
		RECT 230.265 0.000 230.465 0.440 ;
		LAYER M2 ;
		RECT 195.665 0.000 195.865 0.440 ;
		LAYER M3 ;
		RECT 195.665 0.000 195.865 0.440 ;
		LAYER M3 ;
		RECT 200.465 0.000 201.985 0.440 ;
		LAYER M3 ;
		RECT 202.545 0.000 202.745 0.440 ;
		LAYER M1 ;
		RECT 195.655 0.000 195.875 0.440 ;
		LAYER M2 ;
		RECT 192.825 0.000 194.345 0.440 ;
		LAYER M3 ;
		RECT 192.825 0.000 194.345 0.440 ;
		LAYER M1 ;
		RECT 192.815 0.000 194.355 0.440 ;
		LAYER M3 ;
		RECT 194.905 0.000 195.105 0.440 ;
		LAYER M1 ;
		RECT 188.775 0.000 190.755 0.440 ;
		LAYER M2 ;
		RECT 194.905 0.000 195.105 0.440 ;
		LAYER M1 ;
		RECT 194.895 0.000 195.115 0.440 ;
		LAYER M1 ;
		RECT 187.255 0.000 187.475 0.440 ;
		LAYER M3 ;
		RECT 187.265 0.000 187.465 0.440 ;
		LAYER M2 ;
		RECT 187.265 0.000 187.465 0.440 ;
		LAYER M2 ;
		RECT 188.785 0.000 190.745 0.440 ;
		LAYER M1 ;
		RECT 191.295 0.000 191.515 0.440 ;
		LAYER M3 ;
		RECT 191.305 0.000 191.505 0.440 ;
		LAYER M3 ;
		RECT 188.785 0.000 190.745 0.440 ;
		LAYER M2 ;
		RECT 188.025 0.000 188.225 0.440 ;
		LAYER M3 ;
		RECT 188.025 0.000 188.225 0.440 ;
		LAYER M2 ;
		RECT 191.305 0.000 191.505 0.440 ;
		LAYER M1 ;
		RECT 177.425 0.000 183.115 0.440 ;
		LAYER M3 ;
		RECT 177.435 0.000 183.105 0.440 ;
		LAYER M1 ;
		RECT 183.655 0.000 183.875 0.440 ;
		LAYER M1 ;
		RECT 169.625 0.000 170.645 0.440 ;
		LAYER M3 ;
		RECT 169.635 0.000 170.635 0.440 ;
		LAYER M2 ;
		RECT 155.455 0.000 162.835 0.440 ;
		LAYER M3 ;
		RECT 171.715 0.000 172.715 0.440 ;
		LAYER M1 ;
		RECT 173.785 0.000 174.805 0.440 ;
		LAYER M1 ;
		RECT 184.415 0.000 184.635 0.440 ;
		LAYER M2 ;
		RECT 184.425 0.000 184.625 0.440 ;
		LAYER M2 ;
		RECT 185.185 0.000 186.705 0.440 ;
		LAYER M3 ;
		RECT 185.185 0.000 186.705 0.440 ;
		LAYER M3 ;
		RECT 184.425 0.000 184.625 0.440 ;
		LAYER M2 ;
		RECT 183.665 0.000 183.865 0.440 ;
		LAYER M1 ;
		RECT 188.015 0.000 188.235 0.440 ;
		LAYER M1 ;
		RECT 185.175 0.000 186.715 0.440 ;
		LAYER M3 ;
		RECT 183.665 0.000 183.865 0.440 ;
		LAYER M2 ;
		RECT 192.065 0.000 192.265 0.440 ;
		LAYER M3 ;
		RECT 192.065 0.000 192.265 0.440 ;
		LAYER M1 ;
		RECT 192.055 0.000 192.275 0.440 ;
		LAYER M2 ;
		RECT 153.215 0.000 153.775 0.445 ;
		LAYER M1 ;
		RECT 153.205 0.000 153.785 0.445 ;
		LAYER M2 ;
		RECT 154.335 0.000 154.895 0.445 ;
		LAYER M3 ;
		RECT 154.335 0.000 154.895 0.445 ;
		LAYER M3 ;
		RECT 153.215 0.000 153.775 0.445 ;
		LAYER M2 ;
		RECT 152.095 0.000 152.655 0.445 ;
		LAYER M1 ;
		RECT 152.085 0.000 152.665 0.445 ;
		LAYER M1 ;
		RECT 154.325 0.000 154.905 0.445 ;
		LAYER M3 ;
		RECT 152.095 0.000 152.655 0.445 ;
		LAYER M2 ;
		RECT 167.555 0.000 168.555 0.440 ;
		LAYER M3 ;
		RECT 167.555 0.000 168.555 0.440 ;
		LAYER M1 ;
		RECT 167.545 0.000 168.565 0.440 ;
		LAYER M2 ;
		RECT 163.395 0.000 166.995 0.440 ;
		LAYER M3 ;
		RECT 163.395 0.000 166.995 0.440 ;
		LAYER M2 ;
		RECT 169.635 0.000 170.635 0.440 ;
		LAYER M1 ;
		RECT 155.445 0.000 162.845 0.440 ;
		LAYER M3 ;
		RECT 155.455 0.000 162.835 0.440 ;
		LAYER M1 ;
		RECT 163.385 0.000 167.005 0.440 ;
		LAYER M2 ;
		RECT 177.435 0.000 183.105 0.440 ;
		LAYER M3 ;
		RECT 175.875 0.000 176.875 0.440 ;
		LAYER M1 ;
		RECT 175.865 0.000 176.885 0.440 ;
		LAYER M2 ;
		RECT 175.875 0.000 176.875 0.440 ;
		LAYER M2 ;
		RECT 173.795 0.000 174.795 0.440 ;
		LAYER M3 ;
		RECT 173.795 0.000 174.795 0.440 ;
		LAYER M2 ;
		RECT 171.715 0.000 172.715 0.440 ;
		LAYER M1 ;
		RECT 171.705 0.000 172.725 0.440 ;
		LAYER M1 ;
		RECT 242.255 0.000 244.235 0.440 ;
		LAYER M2 ;
		RECT 242.265 0.000 244.225 0.440 ;
		LAYER M3 ;
		RECT 242.265 0.000 244.225 0.440 ;
		LAYER M3 ;
		RECT 294.225 0.000 294.425 0.440 ;
		LAYER M3 ;
		RECT 294.985 0.000 295.185 0.440 ;
		LAYER M1 ;
		RECT 292.135 0.000 293.675 0.440 ;
		LAYER M3 ;
		RECT 290.625 0.000 290.825 0.440 ;
		LAYER M3 ;
		RECT 38.325 0.000 38.525 0.440 ;
		LAYER M1 ;
		RECT 43.875 0.000 45.415 0.440 ;
		LAYER M3 ;
		RECT 45.965 0.000 46.165 0.440 ;
		LAYER M1 ;
		RECT 45.955 0.000 46.175 0.440 ;
		LAYER M2 ;
		RECT 43.885 0.000 45.405 0.440 ;
		LAYER M3 ;
		RECT 43.885 0.000 45.405 0.440 ;
		LAYER M1 ;
		RECT 23.035 0.000 23.255 0.440 ;
		LAYER M3 ;
		RECT 46.725 0.000 46.925 0.440 ;
		LAYER M1 ;
		RECT 46.715 0.000 46.935 0.440 ;
		LAYER M1 ;
		RECT 27.075 0.000 27.295 0.440 ;
		LAYER M1 ;
		RECT 27.835 0.000 28.055 0.440 ;
		LAYER M3 ;
		RECT 42.365 0.000 42.565 0.440 ;
		LAYER M1 ;
		RECT 42.355 0.000 42.575 0.440 ;
		LAYER M1 ;
		RECT 43.115 0.000 43.335 0.440 ;
		LAYER M1 ;
		RECT 39.835 0.000 41.815 0.440 ;
		LAYER M2 ;
		RECT 28.605 0.000 30.125 0.440 ;
		LAYER M3 ;
		RECT 28.605 0.000 30.125 0.440 ;
		LAYER M2 ;
		RECT 27.845 0.000 28.045 0.440 ;
		LAYER M3 ;
		RECT 27.845 0.000 28.045 0.440 ;
		LAYER M1 ;
		RECT 28.595 0.000 30.135 0.440 ;
		LAYER M1 ;
		RECT 30.675 0.000 30.895 0.440 ;
		LAYER M3 ;
		RECT 30.685 0.000 30.885 0.440 ;
		LAYER M2 ;
		RECT 32.205 0.000 34.165 0.440 ;
		LAYER M3 ;
		RECT 32.205 0.000 34.165 0.440 ;
		LAYER M3 ;
		RECT 31.445 0.000 31.645 0.440 ;
		LAYER M1 ;
		RECT 31.435 0.000 31.655 0.440 ;
		LAYER M3 ;
		RECT 68.885 0.000 69.085 0.440 ;
		LAYER M2 ;
		RECT 68.885 0.000 69.085 0.440 ;
		LAYER M2 ;
		RECT 69.645 0.000 69.845 0.440 ;
		LAYER M1 ;
		RECT 73.675 0.000 73.895 0.440 ;
		LAYER M1 ;
		RECT 69.635 0.000 69.855 0.440 ;
		LAYER M2 ;
		RECT 66.045 0.000 66.245 0.440 ;
		LAYER M3 ;
		RECT 66.045 0.000 66.245 0.440 ;
		LAYER M2 ;
		RECT 65.285 0.000 65.485 0.440 ;
		LAYER M3 ;
		RECT 65.285 0.000 65.485 0.440 ;
		LAYER M1 ;
		RECT 66.795 0.000 68.335 0.440 ;
		LAYER M1 ;
		RECT 65.275 0.000 65.495 0.440 ;
		LAYER M3 ;
		RECT 62.765 0.000 64.725 0.440 ;
		LAYER M3 ;
		RECT 66.805 0.000 68.325 0.440 ;
		LAYER M2 ;
		RECT 77.285 0.000 77.485 0.440 ;
		LAYER M1 ;
		RECT 77.275 0.000 77.495 0.440 ;
		LAYER M3 ;
		RECT 74.445 0.000 75.965 0.440 ;
		LAYER M1 ;
		RECT 38.315 0.000 38.535 0.440 ;
		LAYER M2 ;
		RECT 34.725 0.000 34.925 0.440 ;
		LAYER M1 ;
		RECT 35.475 0.000 35.695 0.440 ;
		LAYER M1 ;
		RECT 36.235 0.000 37.775 0.440 ;
		LAYER M2 ;
		RECT 36.245 0.000 37.765 0.440 ;
		LAYER M2 ;
		RECT 35.485 0.000 35.685 0.440 ;
		LAYER M3 ;
		RECT 35.485 0.000 35.685 0.440 ;
		LAYER M3 ;
		RECT 36.245 0.000 37.765 0.440 ;
		LAYER M2 ;
		RECT 39.085 0.000 39.285 0.440 ;
		LAYER M1 ;
		RECT 39.075 0.000 39.295 0.440 ;
		LAYER M3 ;
		RECT 34.725 0.000 34.925 0.440 ;
		LAYER M3 ;
		RECT 39.085 0.000 39.285 0.440 ;
		LAYER M2 ;
		RECT 38.325 0.000 38.525 0.440 ;
		LAYER M1 ;
		RECT 34.715 0.000 34.935 0.440 ;
		LAYER M1 ;
		RECT 32.195 0.000 34.175 0.440 ;
		LAYER M1 ;
		RECT 19.435 0.000 19.655 0.440 ;
		LAYER M3 ;
		RECT 20.965 0.000 22.485 0.440 ;
		LAYER M1 ;
		RECT 20.955 0.000 22.495 0.440 ;
		LAYER M2 ;
		RECT 20.205 0.000 20.405 0.440 ;
		LAYER M3 ;
		RECT 20.205 0.000 20.405 0.440 ;
		LAYER M1 ;
		RECT 20.195 0.000 20.415 0.440 ;
		LAYER M2 ;
		RECT 20.965 0.000 22.485 0.440 ;
		LAYER M1 ;
		RECT 24.555 0.000 26.535 0.440 ;
		LAYER M3 ;
		RECT 24.565 0.000 26.525 0.440 ;
		LAYER M2 ;
		RECT 23.805 0.000 24.005 0.440 ;
		LAYER M1 ;
		RECT 23.795 0.000 24.015 0.440 ;
		LAYER M2 ;
		RECT 24.565 0.000 26.525 0.440 ;
		LAYER M2 ;
		RECT 27.085 0.000 27.285 0.440 ;
		LAYER M3 ;
		RECT 27.085 0.000 27.285 0.440 ;
		LAYER M2 ;
		RECT 23.045 0.000 23.245 0.440 ;
		LAYER M1 ;
		RECT 222.615 0.000 222.835 0.440 ;
		LAYER M3 ;
		RECT 222.625 0.000 222.825 0.440 ;
		LAYER M1 ;
		RECT 221.855 0.000 222.075 0.440 ;
		LAYER M2 ;
		RECT 223.385 0.000 224.905 0.440 ;
		LAYER M3 ;
		RECT 223.385 0.000 224.905 0.440 ;
		LAYER M2 ;
		RECT 240.745 0.000 240.945 0.440 ;
		LAYER M3 ;
		RECT 240.745 0.000 240.945 0.440 ;
		LAYER M1 ;
		RECT 237.895 0.000 238.115 0.440 ;
		LAYER M1 ;
		RECT 237.135 0.000 237.355 0.440 ;
		LAYER M3 ;
		RECT 238.665 0.000 240.185 0.440 ;
		LAYER M1 ;
		RECT 238.655 0.000 240.195 0.440 ;
		LAYER M2 ;
		RECT 237.905 0.000 238.105 0.440 ;
		LAYER M3 ;
		RECT 237.905 0.000 238.105 0.440 ;
		LAYER M2 ;
		RECT 219.345 0.000 221.305 0.440 ;
		LAYER M3 ;
		RECT 219.345 0.000 221.305 0.440 ;
		LAYER M1 ;
		RECT 223.375 0.000 224.915 0.440 ;
		LAYER M1 ;
		RECT 226.215 0.000 226.435 0.440 ;
		LAYER M2 ;
		RECT 226.225 0.000 226.425 0.440 ;
		LAYER M2 ;
		RECT 226.985 0.000 228.945 0.440 ;
		LAYER M1 ;
		RECT 226.975 0.000 228.955 0.440 ;
		LAYER M3 ;
		RECT 226.225 0.000 226.425 0.440 ;
		LAYER M3 ;
		RECT 226.985 0.000 228.945 0.440 ;
		LAYER M1 ;
		RECT 225.455 0.000 225.675 0.440 ;
		LAYER M3 ;
		RECT 234.625 0.000 236.585 0.440 ;
		LAYER M1 ;
		RECT 234.615 0.000 236.595 0.440 ;
		LAYER M2 ;
		RECT 237.145 0.000 237.345 0.440 ;
		LAYER M2 ;
		RECT 225.465 0.000 225.665 0.440 ;
		LAYER M3 ;
		RECT 225.465 0.000 225.665 0.440 ;
		LAYER M3 ;
		RECT 237.145 0.000 237.345 0.440 ;
		LAYER M2 ;
		RECT 234.625 0.000 236.585 0.440 ;
		LAYER M1 ;
		RECT 229.495 0.000 229.715 0.440 ;
		LAYER M3 ;
		RECT 229.505 0.000 229.705 0.440 ;
		LAYER M2 ;
		RECT 230.265 0.000 230.465 0.440 ;
		LAYER M1 ;
		RECT 230.255 0.000 230.475 0.440 ;
		LAYER M2 ;
		RECT 231.025 0.000 232.545 0.440 ;
		LAYER M3 ;
		RECT 231.025 0.000 232.545 0.440 ;
		LAYER M1 ;
		RECT 231.015 0.000 232.555 0.440 ;
		LAYER M2 ;
		RECT 229.505 0.000 229.705 0.440 ;
		LAYER M3 ;
		RECT 233.105 0.000 233.305 0.440 ;
		LAYER M1 ;
		RECT 233.095 0.000 233.315 0.440 ;
		LAYER M1 ;
		RECT 233.855 0.000 234.075 0.440 ;
		LAYER M3 ;
		RECT 233.865 0.000 234.065 0.440 ;
		LAYER M2 ;
		RECT 233.865 0.000 234.065 0.440 ;
		LAYER M2 ;
		RECT 233.105 0.000 233.305 0.440 ;
		LAYER M3 ;
		RECT 215.745 0.000 217.265 0.440 ;
		LAYER M1 ;
		RECT 206.575 0.000 206.795 0.440 ;
		LAYER M2 ;
		RECT 204.065 0.000 206.025 0.440 ;
		LAYER M2 ;
		RECT 203.305 0.000 203.505 0.440 ;
		LAYER M1 ;
		RECT 50.755 0.000 50.975 0.440 ;
		LAYER M2 ;
		RECT 50.765 0.000 50.965 0.440 ;
		LAYER M3 ;
		RECT 50.765 0.000 50.965 0.440 ;
		LAYER M1 ;
		RECT 51.515 0.000 53.055 0.440 ;
		LAYER M2 ;
		RECT 47.485 0.000 49.445 0.440 ;
		LAYER M2 ;
		RECT 122.365 0.000 122.565 0.440 ;
		LAYER M1 ;
		RECT 55.115 0.000 57.095 0.440 ;
		LAYER M3 ;
		RECT 47.485 0.000 49.445 0.440 ;
		LAYER M2 ;
		RECT 50.005 0.000 50.205 0.440 ;
		LAYER M1 ;
		RECT 49.995 0.000 50.215 0.440 ;
		LAYER M1 ;
		RECT 54.355 0.000 54.575 0.440 ;
		LAYER M3 ;
		RECT 50.005 0.000 50.205 0.440 ;
		LAYER M1 ;
		RECT 202.535 0.000 202.755 0.440 ;
		LAYER M1 ;
		RECT 144.145 0.000 151.545 0.440 ;
		LAYER M2 ;
		RECT 144.155 0.000 151.535 0.440 ;
		LAYER M3 ;
		RECT 51.525 0.000 53.045 0.440 ;
		LAYER M1 ;
		RECT 88.195 0.000 88.415 0.440 ;
		LAYER M3 ;
		RECT 88.965 0.000 89.165 0.440 ;
		LAYER M1 ;
		RECT 88.955 0.000 89.175 0.440 ;
		LAYER M2 ;
		RECT 88.965 0.000 89.165 0.440 ;
		LAYER M1 ;
		RECT 104.235 0.000 104.455 0.440 ;
		LAYER M2 ;
		RECT 105.005 0.000 106.525 0.440 ;
		LAYER M1 ;
		RECT 104.995 0.000 106.535 0.440 ;
		LAYER M1 ;
		RECT 118.755 0.000 118.975 0.440 ;
		LAYER M2 ;
		RECT 104.245 0.000 104.445 0.440 ;
		LAYER M1 ;
		RECT 103.475 0.000 103.695 0.440 ;
		LAYER M1 ;
		RECT 82.075 0.000 83.615 0.440 ;
		LAYER M1 ;
		RECT 85.675 0.000 87.655 0.440 ;
		LAYER M2 ;
		RECT 88.205 0.000 88.405 0.440 ;
		LAYER M3 ;
		RECT 88.205 0.000 88.405 0.440 ;
		LAYER M3 ;
		RECT 85.685 0.000 87.645 0.440 ;
		LAYER M3 ;
		RECT 95.845 0.000 96.045 0.440 ;
		LAYER M1 ;
		RECT 97.355 0.000 98.895 0.440 ;
		LAYER M3 ;
		RECT 100.205 0.000 100.405 0.440 ;
		LAYER M3 ;
		RECT 96.605 0.000 96.805 0.440 ;
		LAYER M1 ;
		RECT 100.195 0.000 100.415 0.440 ;
		LAYER M3 ;
		RECT 100.965 0.000 102.925 0.440 ;
		LAYER M2 ;
		RECT 51.525 0.000 53.045 0.440 ;
		LAYER M1 ;
		RECT 53.595 0.000 53.815 0.440 ;
		LAYER M2 ;
		RECT 54.365 0.000 54.565 0.440 ;
		LAYER M3 ;
		RECT 54.365 0.000 54.565 0.440 ;
		LAYER M2 ;
		RECT 53.605 0.000 53.805 0.440 ;
		LAYER M3 ;
		RECT 53.605 0.000 53.805 0.440 ;
		LAYER M1 ;
		RECT 57.635 0.000 57.855 0.440 ;
		LAYER M2 ;
		RECT 55.125 0.000 57.085 0.440 ;
		LAYER M3 ;
		RECT 55.125 0.000 57.085 0.440 ;
		LAYER M3 ;
		RECT 78.045 0.000 80.005 0.440 ;
		LAYER M1 ;
		RECT 78.035 0.000 80.015 0.440 ;
		LAYER M2 ;
		RECT 80.565 0.000 80.765 0.440 ;
		LAYER M3 ;
		RECT 80.565 0.000 80.765 0.440 ;
		LAYER M2 ;
		RECT 59.165 0.000 60.685 0.440 ;
		LAYER M3 ;
		RECT 59.165 0.000 60.685 0.440 ;
		LAYER M3 ;
		RECT 61.245 0.000 61.445 0.440 ;
		LAYER M1 ;
		RECT 61.235 0.000 61.455 0.440 ;
		LAYER M1 ;
		RECT 139.985 0.000 143.605 0.440 ;
		LAYER M3 ;
		RECT 139.995 0.000 143.595 0.440 ;
		LAYER M2 ;
		RECT 139.995 0.000 143.595 0.440 ;
		LAYER M2 ;
		RECT 138.435 0.000 139.435 0.440 ;
		LAYER M3 ;
		RECT 138.435 0.000 139.435 0.440 ;
		LAYER M1 ;
		RECT 136.345 0.000 137.365 0.440 ;
		LAYER M1 ;
		RECT 134.265 0.000 135.285 0.440 ;
		LAYER M3 ;
		RECT 132.195 0.000 133.195 0.440 ;
		LAYER M1 ;
		RECT 132.185 0.000 133.205 0.440 ;
		LAYER M1 ;
		RECT 138.425 0.000 139.445 0.440 ;
		LAYER M1 ;
		RECT 130.105 0.000 131.125 0.440 ;
		LAYER M1 ;
		RECT 123.875 0.000 129.565 0.440 ;
		LAYER M3 ;
		RECT 122.365 0.000 122.565 0.440 ;
		LAYER M3 ;
		RECT 107.085 0.000 107.285 0.440 ;
		LAYER M1 ;
		RECT 107.835 0.000 108.055 0.440 ;
		LAYER M3 ;
		RECT 112.645 0.000 114.165 0.440 ;
		LAYER M3 ;
		RECT 114.725 0.000 114.925 0.440 ;
		LAYER M3 ;
		RECT 107.845 0.000 108.045 0.440 ;
		LAYER M3 ;
		RECT 144.155 0.000 151.535 0.440 ;
		LAYER M1 ;
		RECT 120.275 0.000 121.815 0.440 ;
		LAYER M2 ;
		RECT 119.525 0.000 119.725 0.440 ;
		LAYER M2 ;
		RECT 112.645 0.000 114.165 0.440 ;
		LAYER M3 ;
		RECT 108.605 0.000 110.565 0.440 ;
		LAYER M2 ;
		RECT 108.605 0.000 110.565 0.440 ;
		LAYER M1 ;
		RECT 112.635 0.000 114.175 0.440 ;
		LAYER M2 ;
		RECT 111.885 0.000 112.085 0.440 ;
		LAYER M3 ;
		RECT 111.885 0.000 112.085 0.440 ;
		LAYER M1 ;
		RECT 111.875 0.000 112.095 0.440 ;
		LAYER M3 ;
		RECT 116.245 0.000 118.205 0.440 ;
		LAYER M1 ;
		RECT 116.235 0.000 118.215 0.440 ;
		LAYER M1 ;
		RECT 115.475 0.000 115.695 0.440 ;
		LAYER M2 ;
		RECT 114.725 0.000 114.925 0.440 ;
		LAYER M2 ;
		RECT 115.485 0.000 115.685 0.440 ;
		LAYER M3 ;
		RECT 115.485 0.000 115.685 0.440 ;
		LAYER M3 ;
		RECT 118.765 0.000 118.965 0.440 ;
		LAYER M3 ;
		RECT 119.525 0.000 119.725 0.440 ;
		LAYER M1 ;
		RECT 119.515 0.000 119.735 0.440 ;
		LAYER M2 ;
		RECT 116.245 0.000 118.205 0.440 ;
		LAYER M2 ;
		RECT 118.765 0.000 118.965 0.440 ;
		LAYER M1 ;
		RECT 114.715 0.000 114.935 0.440 ;
		LAYER M3 ;
		RECT 111.125 0.000 111.325 0.440 ;
		LAYER M1 ;
		RECT 111.115 0.000 111.335 0.440 ;
		LAYER M2 ;
		RECT 111.125 0.000 111.325 0.440 ;
		LAYER M3 ;
		RECT 99.445 0.000 99.645 0.440 ;
		LAYER M2 ;
		RECT 99.445 0.000 99.645 0.440 ;
		LAYER M1 ;
		RECT 99.435 0.000 99.655 0.440 ;
		LAYER M2 ;
		RECT 97.365 0.000 98.885 0.440 ;
		LAYER M2 ;
		RECT 100.205 0.000 100.405 0.440 ;
		LAYER M3 ;
		RECT 104.245 0.000 104.445 0.440 ;
		LAYER M2 ;
		RECT 107.085 0.000 107.285 0.440 ;
		LAYER M1 ;
		RECT 107.075 0.000 107.295 0.440 ;
		LAYER M2 ;
		RECT 107.845 0.000 108.045 0.440 ;
		LAYER M3 ;
		RECT 105.005 0.000 106.525 0.440 ;
		LAYER M2 ;
		RECT 103.485 0.000 103.685 0.440 ;
		LAYER M3 ;
		RECT 103.485 0.000 103.685 0.440 ;
		LAYER M2 ;
		RECT 100.965 0.000 102.925 0.440 ;
		LAYER M1 ;
		RECT 100.955 0.000 102.935 0.440 ;
		LAYER M1 ;
		RECT 96.595 0.000 96.815 0.440 ;
		LAYER M2 ;
		RECT 96.605 0.000 96.805 0.440 ;
		LAYER M3 ;
		RECT 97.365 0.000 98.885 0.440 ;
		LAYER M2 ;
		RECT 93.325 0.000 95.285 0.440 ;
		LAYER M3 ;
		RECT 92.565 0.000 92.765 0.440 ;
		LAYER M3 ;
		RECT 89.725 0.000 91.245 0.440 ;
		LAYER M1 ;
		RECT 89.715 0.000 91.255 0.440 ;
		LAYER M2 ;
		RECT 89.725 0.000 91.245 0.440 ;
		LAYER M1 ;
		RECT 81.315 0.000 81.535 0.440 ;
		LAYER M2 ;
		RECT 81.325 0.000 81.525 0.440 ;
		LAYER M3 ;
		RECT 81.325 0.000 81.525 0.440 ;
		LAYER M1 ;
		RECT 80.555 0.000 80.775 0.440 ;
		LAYER M3 ;
		RECT 77.285 0.000 77.485 0.440 ;
		LAYER M2 ;
		RECT 76.525 0.000 76.725 0.440 ;
		LAYER M3 ;
		RECT 76.525 0.000 76.725 0.440 ;
		LAYER M2 ;
		RECT 78.045 0.000 80.005 0.440 ;
		LAYER M2 ;
		RECT 85.685 0.000 87.645 0.440 ;
		LAYER M2 ;
		RECT 84.925 0.000 85.125 0.440 ;
		LAYER M2 ;
		RECT 84.165 0.000 84.365 0.440 ;
		LAYER M1 ;
		RECT 123.115 0.000 123.335 0.440 ;
		LAYER M2 ;
		RECT 120.285 0.000 121.805 0.440 ;
		LAYER M1 ;
		RECT 95.835 0.000 96.055 0.440 ;
		LAYER M3 ;
		RECT 120.285 0.000 121.805 0.440 ;
		LAYER M1 ;
		RECT 108.595 0.000 110.575 0.440 ;
		LAYER M1 ;
		RECT 122.355 0.000 122.575 0.440 ;
		LAYER M3 ;
		RECT 93.325 0.000 95.285 0.440 ;
		LAYER M2 ;
		RECT 82.085 0.000 83.605 0.440 ;
		LAYER M3 ;
		RECT 84.925 0.000 85.125 0.440 ;
		LAYER M3 ;
		RECT 84.165 0.000 84.365 0.440 ;
		LAYER M1 ;
		RECT 84.155 0.000 84.375 0.440 ;
		LAYER M1 ;
		RECT 84.915 0.000 85.135 0.440 ;
		LAYER M3 ;
		RECT 82.085 0.000 83.605 0.440 ;
		LAYER M2 ;
		RECT 74.445 0.000 75.965 0.440 ;
		LAYER M1 ;
		RECT 76.515 0.000 76.735 0.440 ;
		LAYER M1 ;
		RECT 93.315 0.000 95.295 0.440 ;
		LAYER M2 ;
		RECT 91.805 0.000 92.005 0.440 ;
		LAYER M3 ;
		RECT 91.805 0.000 92.005 0.440 ;
		LAYER M1 ;
		RECT 91.795 0.000 92.015 0.440 ;
		LAYER M2 ;
		RECT 92.565 0.000 92.765 0.440 ;
		LAYER M1 ;
		RECT 92.555 0.000 92.775 0.440 ;
		LAYER M1 ;
		RECT 74.435 0.000 75.975 0.440 ;
		LAYER M2 ;
		RECT 73.685 0.000 73.885 0.440 ;
		LAYER M3 ;
		RECT 73.685 0.000 73.885 0.440 ;
		LAYER M2 ;
		RECT 95.845 0.000 96.045 0.440 ;
		LAYER M1 ;
		RECT 279.695 0.000 279.915 0.440 ;
		LAYER M2 ;
		RECT 278.945 0.000 279.145 0.440 ;
		LAYER M1 ;
		RECT 278.935 0.000 279.155 0.440 ;
		LAYER M2 ;
		RECT 276.865 0.000 278.385 0.440 ;
		LAYER M1 ;
		RECT 275.335 0.000 275.555 0.440 ;
		LAYER M1 ;
		RECT 276.095 0.000 276.315 0.440 ;
		LAYER M1 ;
		RECT 276.855 0.000 278.395 0.440 ;
		LAYER M1 ;
		RECT 280.455 0.000 282.435 0.440 ;
		LAYER M3 ;
		RECT 282.985 0.000 283.185 0.440 ;
		LAYER M1 ;
		RECT 282.975 0.000 283.195 0.440 ;
		LAYER M2 ;
		RECT 284.505 0.000 286.025 0.440 ;
		LAYER M3 ;
		RECT 284.505 0.000 286.025 0.440 ;
		LAYER M2 ;
		RECT 275.345 0.000 275.545 0.440 ;
		LAYER M2 ;
		RECT 286.585 0.000 286.785 0.440 ;
		LAYER M3 ;
		RECT 286.585 0.000 286.785 0.440 ;
		LAYER M1 ;
		RECT 302.615 0.000 302.835 0.440 ;
		LAYER M3 ;
		RECT 4.165 0.000 4.365 0.440 ;
		LAYER M2 ;
		RECT 4.165 0.000 4.365 0.440 ;
		LAYER M1 ;
		RECT 4.915 0.000 5.135 0.440 ;
		LAYER M3 ;
		RECT 23.045 0.000 23.245 0.440 ;
		LAYER M3 ;
		RECT 16.165 0.000 16.365 0.440 ;
		LAYER M1 ;
		RECT 16.155 0.000 16.375 0.440 ;
		LAYER M2 ;
		RECT 11.805 0.000 12.005 0.440 ;
		LAYER M1 ;
		RECT 11.795 0.000 12.015 0.440 ;
		LAYER M1 ;
		RECT 12.555 0.000 12.775 0.440 ;
		LAYER M3 ;
		RECT 15.405 0.000 15.605 0.440 ;
		LAYER M2 ;
		RECT 9.285 0.000 11.245 0.440 ;
		LAYER M1 ;
		RECT 7.755 0.000 7.975 0.440 ;
		LAYER M2 ;
		RECT 5.685 0.000 7.205 0.440 ;
		LAYER M3 ;
		RECT 5.685 0.000 7.205 0.440 ;
		LAYER M2 ;
		RECT 4.925 0.000 5.125 0.440 ;
		LAYER M3 ;
		RECT 4.925 0.000 5.125 0.440 ;
		LAYER M1 ;
		RECT 5.675 0.000 7.215 0.440 ;
		LAYER M1 ;
		RECT 303.375 0.000 306.890 0.440 ;
		LAYER M2 ;
		RECT 303.385 0.000 306.890 0.440 ;
		LAYER M3 ;
		RECT 303.385 0.000 306.890 0.440 ;
		LAYER M2 ;
		RECT 16.925 0.000 18.885 0.440 ;
		LAYER M1 ;
		RECT 16.915 0.000 18.895 0.440 ;
		LAYER M2 ;
		RECT 19.445 0.000 19.645 0.440 ;
		LAYER M3 ;
		RECT 19.445 0.000 19.645 0.440 ;
		LAYER M3 ;
		RECT 16.925 0.000 18.885 0.440 ;
		LAYER M2 ;
		RECT 31.445 0.000 31.645 0.440 ;
		LAYER M2 ;
		RECT 30.685 0.000 30.885 0.440 ;
		LAYER M1 ;
		RECT 47.475 0.000 49.455 0.440 ;
		LAYER M3 ;
		RECT 23.805 0.000 24.005 0.440 ;
		LAYER M2 ;
		RECT 42.365 0.000 42.565 0.440 ;
		LAYER M2 ;
		RECT 39.845 0.000 41.805 0.440 ;
		LAYER M3 ;
		RECT 39.845 0.000 41.805 0.440 ;
		LAYER M2 ;
		RECT 46.725 0.000 46.925 0.440 ;
		LAYER M2 ;
		RECT 45.965 0.000 46.165 0.440 ;
		LAYER M2 ;
		RECT 43.125 0.000 43.325 0.440 ;
		LAYER M3 ;
		RECT 43.125 0.000 43.325 0.440 ;
		LAYER M1 ;
		RECT 9.275 0.000 11.255 0.440 ;
		LAYER M3 ;
		RECT 11.805 0.000 12.005 0.440 ;
		LAYER M2 ;
		RECT 12.565 0.000 12.765 0.440 ;
		LAYER M3 ;
		RECT 12.565 0.000 12.765 0.440 ;
		LAYER M3 ;
		RECT 8.525 0.000 8.725 0.440 ;
		LAYER M1 ;
		RECT 8.515 0.000 8.735 0.440 ;
		LAYER M2 ;
		RECT 7.765 0.000 7.965 0.440 ;
		LAYER M3 ;
		RECT 7.765 0.000 7.965 0.440 ;
		LAYER M2 ;
		RECT 8.525 0.000 8.725 0.440 ;
		LAYER M3 ;
		RECT 9.285 0.000 11.245 0.440 ;
		LAYER M1 ;
		RECT 15.395 0.000 15.615 0.440 ;
		LAYER M2 ;
		RECT 16.165 0.000 16.365 0.440 ;
		LAYER M1 ;
		RECT 13.315 0.000 14.855 0.440 ;
		LAYER M2 ;
		RECT 13.325 0.000 14.845 0.440 ;
		LAYER M3 ;
		RECT 13.325 0.000 14.845 0.440 ;
		LAYER M2 ;
		RECT 15.405 0.000 15.605 0.440 ;
		LAYER M1 ;
		RECT 66.035 0.000 66.255 0.440 ;
		LAYER M2 ;
		RECT 66.805 0.000 68.325 0.440 ;
		LAYER M2 ;
		RECT 70.405 0.000 72.365 0.440 ;
		LAYER M3 ;
		RECT 70.405 0.000 72.365 0.440 ;
		LAYER M1 ;
		RECT 68.875 0.000 69.095 0.440 ;
		LAYER M3 ;
		RECT 69.645 0.000 69.845 0.440 ;
		LAYER M1 ;
		RECT 61.995 0.000 62.215 0.440 ;
		LAYER M2 ;
		RECT 62.765 0.000 64.725 0.440 ;
		LAYER M1 ;
		RECT 62.755 0.000 64.735 0.440 ;
		LAYER M2 ;
		RECT 62.005 0.000 62.205 0.440 ;
		LAYER M3 ;
		RECT 62.005 0.000 62.205 0.440 ;
		LAYER M1 ;
		RECT 70.395 0.000 72.375 0.440 ;
		LAYER M2 ;
		RECT 72.925 0.000 73.125 0.440 ;
		LAYER M1 ;
		RECT 72.915 0.000 73.135 0.440 ;
		LAYER M3 ;
		RECT 72.925 0.000 73.125 0.440 ;
		LAYER M5 ;
		RECT 182.125 26.330 304.770 28.490 ;
		LAYER VIA5 ;
		RECT 182.125 26.330 304.770 28.490 ;
		LAYER M2 ;
		RECT 155.455 0.440 306.890 0.445 ;
		LAYER M3 ;
		RECT 155.455 0.440 306.890 0.445 ;
		LAYER M5 ;
		RECT 2.220 26.330 124.865 28.490 ;
		LAYER VIA5 ;
		RECT 2.220 26.330 124.865 28.490 ;
		LAYER M1 ;
		RECT 155.445 0.440 306.890 0.445 ;
		LAYER M5 ;
		RECT 0.000 38.710 127.175 173.370 ;
		LAYER M4 ;
		RECT 0.100 14.900 306.890 184.850 ;
		LAYER VIA2 ;
		RECT 0.100 0.560 306.890 184.850 ;
		LAYER M2 ;
		RECT 3.605 0.440 151.535 184.850 ;
		LAYER M1 ;
		RECT 58.395 0.000 58.615 0.440 ;
		LAYER M3 ;
		RECT 58.405 0.000 58.605 0.440 ;
		LAYER M2 ;
		RECT 58.405 0.000 58.605 0.440 ;
		LAYER M1 ;
		RECT 59.155 0.000 60.695 0.440 ;
		LAYER M3 ;
		RECT 57.645 0.000 57.845 0.440 ;
		LAYER M2 ;
		RECT 57.645 0.000 57.845 0.440 ;
		LAYER M2 ;
		RECT 61.245 0.000 61.445 0.440 ;
		LAYER M2 ;
		RECT 123.125 0.000 123.325 0.440 ;
		LAYER M2 ;
		RECT 123.885 0.000 129.555 0.440 ;
		LAYER M3 ;
		RECT 123.885 0.000 129.555 0.440 ;
		LAYER M3 ;
		RECT 130.115 0.000 131.115 0.440 ;
		LAYER M2 ;
		RECT 130.115 0.000 131.115 0.440 ;
		LAYER M2 ;
		RECT 134.275 0.000 135.275 0.440 ;
		LAYER M3 ;
		RECT 134.275 0.000 135.275 0.440 ;
		LAYER M2 ;
		RECT 136.355 0.000 137.355 0.440 ;
		LAYER M3 ;
		RECT 123.125 0.000 123.325 0.440 ;
		LAYER M2 ;
		RECT 132.195 0.000 133.195 0.440 ;
		LAYER M3 ;
		RECT 136.355 0.000 137.355 0.440 ;
		LAYER M3 ;
		RECT 3.605 0.440 151.535 184.850 ;
		LAYER M1 ;
		RECT 4.155 0.000 4.375 0.440 ;
		LAYER M1 ;
		RECT 0.100 0.000 3.615 184.850 ;
		LAYER VIA5 ;
		RECT 1.880 38.640 127.175 173.440 ;
		LAYER M1 ;
		RECT 3.615 0.440 151.545 184.850 ;
		LAYER M2 ;
		RECT 0.100 0.000 3.605 184.850 ;
		LAYER M3 ;
		RECT 0.100 0.000 3.605 184.850 ;
		LAYER M2 ;
		RECT 151.535 0.445 306.890 184.850 ;
		LAYER VIA3 ;
		RECT 0.100 0.560 306.890 184.850 ;
		LAYER VIA4 ;
		RECT 0.100 14.900 306.890 184.850 ;
		LAYER VIA1 ;
		RECT 0.100 0.560 306.890 184.850 ;
		LAYER VIA5 ;
		RECT 179.815 38.640 305.110 173.440 ;
		LAYER M5 ;
		RECT 179.815 38.710 306.990 173.370 ;
		LAYER M1 ;
		RECT 151.545 0.445 306.890 184.850 ;
		LAYER M3 ;
		RECT 151.535 0.445 306.890 184.850 ;
	END
	# End of OBS

END TSDN65LPLLA1024X32M4S

END LIBRARY
